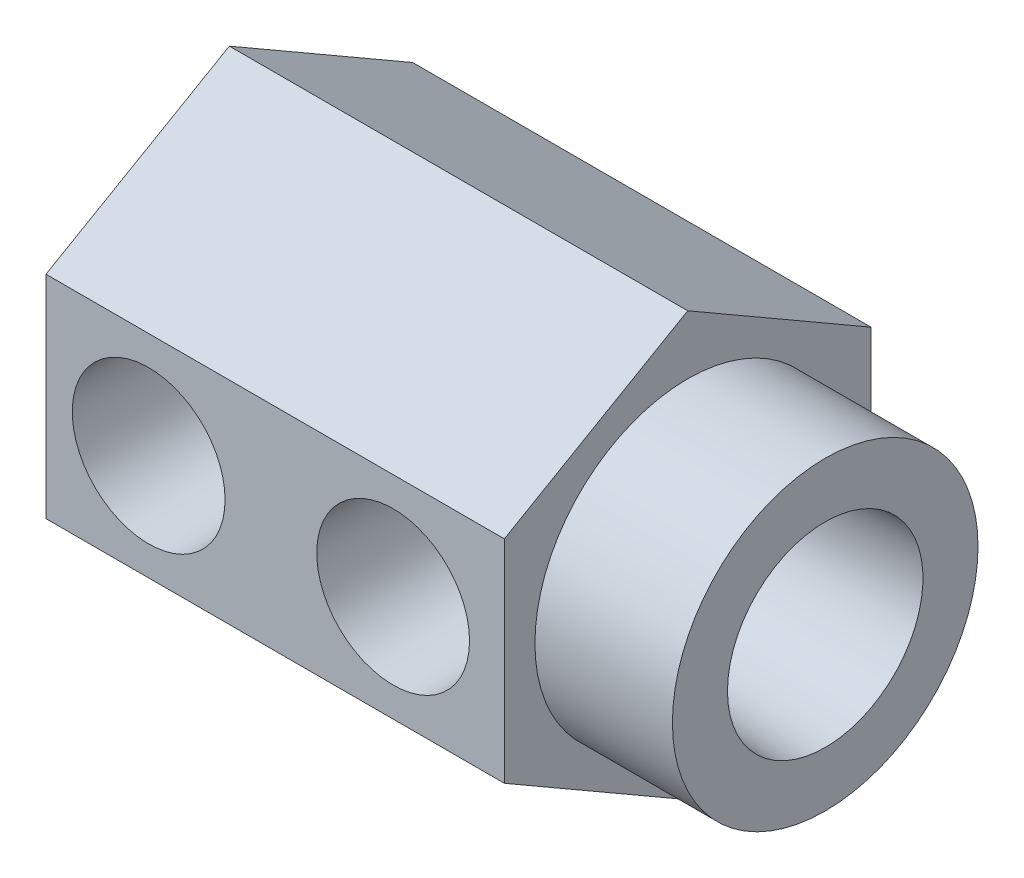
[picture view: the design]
ISO-10303-21;
HEADER;
FILE_DESCRIPTION(('STEP AP214'),'2;1');
FILE_NAME('part.step','',(''),(''),'','','');
FILE_SCHEMA(('AUTOMOTIVE_DESIGN { 1 0 10303 214 1 1 1 1 }'));
ENDSEC;
DATA;
#1=APPLICATION_CONTEXT('core data for automotive mechanical design processes');
#2=APPLICATION_PROTOCOL_DEFINITION('international standard','automotive_design',2000,#1);
#3=PRODUCT_CONTEXT('',#1,'mechanical');
#4=PRODUCT('Part','Part','',(#3));
#5=PRODUCT_RELATED_PRODUCT_CATEGORY('part','',(#4));
#6=PRODUCT_DEFINITION_FORMATION('','',#4);
#7=PRODUCT_DEFINITION_CONTEXT('part definition',#1,'design');
#8=PRODUCT_DEFINITION('design','',#6,#7);
#9=PRODUCT_DEFINITION_SHAPE('','',#8);
#10=(LENGTH_UNIT() NAMED_UNIT(*) SI_UNIT(.MILLI.,.METRE.));
#11=(NAMED_UNIT(*) PLANE_ANGLE_UNIT() SI_UNIT($,.RADIAN.));
#12=(NAMED_UNIT(*) SI_UNIT($,.STERADIAN.) SOLID_ANGLE_UNIT());
#13=UNCERTAINTY_MEASURE_WITH_UNIT(LENGTH_MEASURE(1.E-05),#10,'distance_accuracy_value','');
#14=(GEOMETRIC_REPRESENTATION_CONTEXT(3) GLOBAL_UNCERTAINTY_ASSIGNED_CONTEXT((#13)) GLOBAL_UNIT_ASSIGNED_CONTEXT((#10,
#11,#12)) REPRESENTATION_CONTEXT('',''));
#15=CARTESIAN_POINT('',(0.,0.,0.));
#16=DIRECTION('',(0.,0.,1.));
#17=DIRECTION('',(1.,0.,0.));
#18=AXIS2_PLACEMENT_3D('',#15,#16,#17);
#19=CARTESIAN_POINT('',(30.95625,0.,0.));
#20=DIRECTION('',(1.,0.,0.));
#21=DIRECTION('',(0.,0.,-1.));
#22=AXIS2_PLACEMENT_3D('',#19,#20,#21);
#23=PLANE('',#22);
#24=CARTESIAN_POINT('',(30.95625,0.,0.));
#25=DIRECTION('',(1.,0.,0.));
#26=DIRECTION('',(0.,0.,-1.));
#27=AXIS2_PLACEMENT_3D('',#24,#25,#26);
#28=CIRCLE('',#27,7.9375);
#29=CARTESIAN_POINT('',(30.95625,0.,-7.9375));
#30=VERTEX_POINT('',#29);
#31=EDGE_CURVE('E138',#30,#30,#28,.T.);
#32=ORIENTED_EDGE('',*,*,#31,.T.);
#33=EDGE_LOOP('',(#32));
#34=FACE_BOUND('',#33,.T.);
#35=CARTESIAN_POINT('',(30.95625,0.,0.));
#36=DIRECTION('',(-1.,0.,0.));
#37=DIRECTION('',(0.,0.,1.));
#38=AXIS2_PLACEMENT_3D('',#35,#36,#37);
#39=CIRCLE('',#38,5.07746);
#40=CARTESIAN_POINT('',(30.95625,0.,5.07746));
#41=VERTEX_POINT('',#40);
#42=EDGE_CURVE('E364',#41,#41,#39,.T.);
#43=ORIENTED_EDGE('',*,*,#42,.T.);
#44=EDGE_LOOP('',(#43));
#45=FACE_BOUND('',#44,.T.);
#46=ADVANCED_FACE('F34',(#34,#45),#23,.T.);
#47=CARTESIAN_POINT('',(23.8125,-5.4992613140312,-9.525));
#48=DIRECTION('',(1.,0.,0.));
#49=DIRECTION('',(0.,0.,-1.));
#50=AXIS2_PLACEMENT_3D('',#47,#48,#49);
#51=PLANE('',#50);
#52=DIRECTION('',(0.,0.5,-0.866025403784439));
#53=VECTOR('',#52,1.);
#54=CARTESIAN_POINT('',(23.8125,-10.9985226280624,0.));
#55=LINE('',#54,#53);
#56=CARTESIAN_POINT('',(23.8125,-10.9985226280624,0.));
#57=VERTEX_POINT('',#56);
#58=CARTESIAN_POINT('',(23.8125,-5.49926131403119,-9.525));
#59=VERTEX_POINT('',#58);
#60=EDGE_CURVE('E146',#57,#59,#55,.T.);
#61=ORIENTED_EDGE('',*,*,#60,.T.);
#62=DIRECTION('',(0.,1.,0.));
#63=VECTOR('',#62,1.);
#64=CARTESIAN_POINT('',(23.8125,-5.49926131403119,-9.525));
#65=LINE('',#64,#63);
#66=CARTESIAN_POINT('',(23.8125,5.49926131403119,-9.525));
#67=VERTEX_POINT('',#66);
#68=EDGE_CURVE('E96',#59,#67,#65,.T.);
#69=ORIENTED_EDGE('',*,*,#68,.T.);
#70=DIRECTION('',(0.,0.5,0.866025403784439));
#71=VECTOR('',#70,1.);
#72=CARTESIAN_POINT('',(23.8125,5.49926131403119,-9.525));
#73=LINE('',#72,#71);
#74=CARTESIAN_POINT('',(23.8125,10.9985226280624,0.));
#75=VERTEX_POINT('',#74);
#76=EDGE_CURVE('E113',#67,#75,#73,.T.);
#77=ORIENTED_EDGE('',*,*,#76,.T.);
#78=DIRECTION('',(0.,-0.5,0.866025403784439));
#79=VECTOR('',#78,1.);
#80=CARTESIAN_POINT('',(23.8125,10.9985226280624,0.));
#81=LINE('',#80,#79);
#82=CARTESIAN_POINT('',(23.8125,5.49926131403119,9.52500000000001));
#83=VERTEX_POINT('',#82);
#84=EDGE_CURVE('E105',#75,#83,#81,.T.);
#85=ORIENTED_EDGE('',*,*,#84,.T.);
#86=DIRECTION('',(0.,-1.,0.));
#87=VECTOR('',#86,1.);
#88=CARTESIAN_POINT('',(23.8125,5.49926131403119,9.52500000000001));
#89=LINE('',#88,#87);
#90=CARTESIAN_POINT('',(23.8125,-5.49926131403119,9.52500000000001));
#91=VERTEX_POINT('',#90);
#92=EDGE_CURVE('E110',#83,#91,#89,.T.);
#93=ORIENTED_EDGE('',*,*,#92,.T.);
#94=DIRECTION('',(0.,-0.5,-0.866025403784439));
#95=VECTOR('',#94,1.);
#96=CARTESIAN_POINT('',(23.8125,-5.49926131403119,9.52500000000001));
#97=LINE('',#96,#95);
#98=EDGE_CURVE('E60',#91,#57,#97,.T.);
#99=ORIENTED_EDGE('',*,*,#98,.T.);
#100=EDGE_LOOP('',(#61,#69,#77,#85,#93,#99));
#101=FACE_BOUND('',#100,.T.);
#102=CARTESIAN_POINT('',(23.8125,0.,0.));
#103=DIRECTION('',(1.,0.,0.));
#104=DIRECTION('',(0.,0.,-1.));
#105=AXIS2_PLACEMENT_3D('',#102,#103,#104);
#106=CIRCLE('',#105,7.9375);
#107=CARTESIAN_POINT('',(23.8125,0.,-7.9375));
#108=VERTEX_POINT('',#107);
#109=EDGE_CURVE('E361',#108,#108,#106,.T.);
#110=ORIENTED_EDGE('',*,*,#109,.F.);
#111=EDGE_LOOP('',(#110));
#112=FACE_BOUND('',#111,.T.);
#113=ADVANCED_FACE('F107',(#101,#112),#51,.T.);
#114=CARTESIAN_POINT('',(23.8125,-10.9985226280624,0.));
#115=DIRECTION('',(0.,0.866025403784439,0.5));
#116=DIRECTION('',(0.,-0.5,0.866025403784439));
#117=AXIS2_PLACEMENT_3D('',#114,#115,#116);
#118=PLANE('',#117);
#119=DIRECTION('',(0.,0.5,-0.866025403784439));
#120=VECTOR('',#119,1.);
#121=CARTESIAN_POINT('',(0.,-10.9985226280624,0.));
#122=LINE('',#121,#120);
#123=CARTESIAN_POINT('',(0.,-10.9985226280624,0.));
#124=VERTEX_POINT('',#123);
#125=CARTESIAN_POINT('',(0.,-5.49926131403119,-9.525));
#126=VERTEX_POINT('',#125);
#127=EDGE_CURVE('E134',#124,#126,#122,.T.);
#128=ORIENTED_EDGE('',*,*,#127,.T.);
#129=DIRECTION('',(-1.,0.,0.));
#130=VECTOR('',#129,1.);
#131=CARTESIAN_POINT('',(23.8125,-5.49926131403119,-9.525));
#132=LINE('',#131,#130);
#133=EDGE_CURVE('E153',#59,#126,#132,.T.);
#134=ORIENTED_EDGE('',*,*,#133,.F.);
#135=ORIENTED_EDGE('',*,*,#60,.F.);
#136=DIRECTION('',(-1.,0.,0.));
#137=VECTOR('',#136,1.);
#138=CARTESIAN_POINT('',(23.8125,-10.9985226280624,0.));
#139=LINE('',#138,#137);
#140=EDGE_CURVE('E130',#57,#124,#139,.T.);
#141=ORIENTED_EDGE('',*,*,#140,.T.);
#142=EDGE_LOOP('',(#128,#134,#135,#141));
#143=FACE_BOUND('',#142,.T.);
#144=ADVANCED_FACE('F36',(#143),#118,.F.);
#145=CARTESIAN_POINT('',(23.8125,-5.49926131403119,-9.525));
#146=DIRECTION('',(0.,0.,1.));
#147=DIRECTION('',(1.,0.,0.));
#148=AXIS2_PLACEMENT_3D('',#145,#146,#147);
#149=PLANE('',#148);
#150=CARTESIAN_POINT('',(5.334,0.,-9.525));
#151=DIRECTION('',(0.,0.,-1.));
#152=DIRECTION('',(-1.,0.,0.));
#153=AXIS2_PLACEMENT_3D('',#150,#151,#152);
#154=CIRCLE('',#153,3.96875);
#155=CARTESIAN_POINT('',(1.36525,0.,-9.525));
#156=VERTEX_POINT('',#155);
#157=EDGE_CURVE('E204',#156,#156,#154,.T.);
#158=ORIENTED_EDGE('',*,*,#157,.F.);
#159=EDGE_LOOP('',(#158));
#160=FACE_BOUND('',#159,.T.);
#161=DIRECTION('',(0.,1.,0.));
#162=VECTOR('',#161,1.);
#163=CARTESIAN_POINT('',(0.,-5.49926131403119,-9.525));
#164=LINE('',#163,#162);
#165=CARTESIAN_POINT('',(0.,5.49926131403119,-9.525));
#166=VERTEX_POINT('',#165);
#167=EDGE_CURVE('E137',#126,#166,#164,.T.);
#168=ORIENTED_EDGE('',*,*,#167,.T.);
#169=DIRECTION('',(-1.,0.,0.));
#170=VECTOR('',#169,1.);
#171=CARTESIAN_POINT('',(23.8125,5.49926131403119,-9.525));
#172=LINE('',#171,#170);
#173=EDGE_CURVE('E150',#67,#166,#172,.T.);
#174=ORIENTED_EDGE('',*,*,#173,.F.);
#175=ORIENTED_EDGE('',*,*,#68,.F.);
#176=ORIENTED_EDGE('',*,*,#133,.T.);
#177=EDGE_LOOP('',(#168,#174,#175,#176));
#178=FACE_BOUND('',#177,.T.);
#179=ADVANCED_FACE('F344',(#160,#178),#149,.F.);
#180=CARTESIAN_POINT('',(23.8125,5.49926131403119,-9.525));
#181=DIRECTION('',(0.,-0.866025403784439,0.5));
#182=DIRECTION('',(0.,-0.5,-0.866025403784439));
#183=AXIS2_PLACEMENT_3D('',#180,#181,#182);
#184=PLANE('',#183);
#185=DIRECTION('',(0.,0.5,0.866025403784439));
#186=VECTOR('',#185,1.);
#187=CARTESIAN_POINT('',(0.,5.49926131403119,-9.525));
#188=LINE('',#187,#186);
#189=CARTESIAN_POINT('',(0.,10.9985226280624,0.));
#190=VERTEX_POINT('',#189);
#191=EDGE_CURVE('E140',#166,#190,#188,.T.);
#192=ORIENTED_EDGE('',*,*,#191,.T.);
#193=DIRECTION('',(-1.,0.,0.));
#194=VECTOR('',#193,1.);
#195=CARTESIAN_POINT('',(23.8125,10.9985226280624,0.));
#196=LINE('',#195,#194);
#197=EDGE_CURVE('E125',#75,#190,#196,.T.);
#198=ORIENTED_EDGE('',*,*,#197,.F.);
#199=ORIENTED_EDGE('',*,*,#76,.F.);
#200=ORIENTED_EDGE('',*,*,#173,.T.);
#201=EDGE_LOOP('',(#192,#198,#199,#200));
#202=FACE_BOUND('',#201,.T.);
#203=ADVANCED_FACE('F342',(#202),#184,.F.);
#204=CARTESIAN_POINT('',(23.8125,10.9985226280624,0.));
#205=DIRECTION('',(0.,-0.866025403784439,-0.5));
#206=DIRECTION('',(0.,0.5,-0.866025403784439));
#207=AXIS2_PLACEMENT_3D('',#204,#205,#206);
#208=PLANE('',#207);
#209=DIRECTION('',(0.,-0.5,0.866025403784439));
#210=VECTOR('',#209,1.);
#211=CARTESIAN_POINT('',(0.,10.9985226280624,0.));
#212=LINE('',#211,#210);
#213=CARTESIAN_POINT('',(0.,5.49926131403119,9.52500000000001));
#214=VERTEX_POINT('',#213);
#215=EDGE_CURVE('E122',#190,#214,#212,.T.);
#216=ORIENTED_EDGE('',*,*,#215,.T.);
#217=DIRECTION('',(-1.,0.,0.));
#218=VECTOR('',#217,1.);
#219=CARTESIAN_POINT('',(23.8125,5.49926131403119,9.52500000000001));
#220=LINE('',#219,#218);
#221=EDGE_CURVE('E119',#83,#214,#220,.T.);
#222=ORIENTED_EDGE('',*,*,#221,.F.);
#223=ORIENTED_EDGE('',*,*,#84,.F.);
#224=ORIENTED_EDGE('',*,*,#197,.T.);
#225=EDGE_LOOP('',(#216,#222,#223,#224));
#226=FACE_BOUND('',#225,.T.);
#227=ADVANCED_FACE('F120',(#226),#208,.F.);
#228=CARTESIAN_POINT('',(23.8125,5.49926131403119,9.52500000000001));
#229=DIRECTION('',(0.,0.,-1.));
#230=DIRECTION('',(-1.,0.,0.));
#231=AXIS2_PLACEMENT_3D('',#228,#229,#230);
#232=PLANE('',#231);
#233=CARTESIAN_POINT('',(5.334,0.,9.52500000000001));
#234=DIRECTION('',(0.,0.,1.));
#235=DIRECTION('',(1.,0.,0.));
#236=AXIS2_PLACEMENT_3D('',#233,#234,#235);
#237=CIRCLE('',#236,3.96875);
#238=CARTESIAN_POINT('',(9.30275,0.,9.52500000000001));
#239=VERTEX_POINT('',#238);
#240=EDGE_CURVE('E278',#239,#239,#237,.T.);
#241=ORIENTED_EDGE('',*,*,#240,.F.);
#242=EDGE_LOOP('',(#241));
#243=FACE_BOUND('',#242,.T.);
#244=CARTESIAN_POINT('',(18.034,0.,9.52500000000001));
#245=DIRECTION('',(0.,0.,1.));
#246=DIRECTION('',(1.,0.,0.));
#247=AXIS2_PLACEMENT_3D('',#244,#245,#246);
#248=CIRCLE('',#247,3.96875);
#249=CARTESIAN_POINT('',(22.00275,0.,9.52500000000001));
#250=VERTEX_POINT('',#249);
#251=EDGE_CURVE('E265',#250,#250,#248,.T.);
#252=ORIENTED_EDGE('',*,*,#251,.F.);
#253=EDGE_LOOP('',(#252));
#254=FACE_BOUND('',#253,.T.);
#255=DIRECTION('',(0.,-1.,0.));
#256=VECTOR('',#255,1.);
#257=CARTESIAN_POINT('',(0.,5.49926131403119,9.52500000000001));
#258=LINE('',#257,#256);
#259=CARTESIAN_POINT('',(0.,-5.49926131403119,9.52500000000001));
#260=VERTEX_POINT('',#259);
#261=EDGE_CURVE('E143',#214,#260,#258,.T.);
#262=ORIENTED_EDGE('',*,*,#261,.T.);
#263=DIRECTION('',(-1.,0.,0.));
#264=VECTOR('',#263,1.);
#265=CARTESIAN_POINT('',(23.8125,-5.49926131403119,9.52500000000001));
#266=LINE('',#265,#264);
#267=EDGE_CURVE('E126',#91,#260,#266,.T.);
#268=ORIENTED_EDGE('',*,*,#267,.F.);
#269=ORIENTED_EDGE('',*,*,#92,.F.);
#270=ORIENTED_EDGE('',*,*,#221,.T.);
#271=EDGE_LOOP('',(#262,#268,#269,#270));
#272=FACE_BOUND('',#271,.T.);
#273=ADVANCED_FACE('F128',(#243,#254,#272),#232,.F.);
#274=CARTESIAN_POINT('',(23.8125,-5.49926131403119,9.52500000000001));
#275=DIRECTION('',(0.,0.866025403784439,-0.5));
#276=DIRECTION('',(0.,0.5,0.866025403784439));
#277=AXIS2_PLACEMENT_3D('',#274,#275,#276);
#278=PLANE('',#277);
#279=DIRECTION('',(0.,-0.5,-0.866025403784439));
#280=VECTOR('',#279,1.);
#281=CARTESIAN_POINT('',(0.,-5.49926131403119,9.52500000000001));
#282=LINE('',#281,#280);
#283=EDGE_CURVE('E87',#260,#124,#282,.T.);
#284=ORIENTED_EDGE('',*,*,#283,.T.);
#285=ORIENTED_EDGE('',*,*,#140,.F.);
#286=ORIENTED_EDGE('',*,*,#98,.F.);
#287=ORIENTED_EDGE('',*,*,#267,.T.);
#288=EDGE_LOOP('',(#284,#285,#286,#287));
#289=FACE_BOUND('',#288,.T.);
#290=ADVANCED_FACE('F333',(#289),#278,.F.);
#291=CARTESIAN_POINT('',(0.,-5.4992613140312,-9.525));
#292=DIRECTION('',(1.,0.,0.));
#293=DIRECTION('',(0.,0.,-1.));
#294=AXIS2_PLACEMENT_3D('',#291,#292,#293);
#295=PLANE('',#294);
#296=ORIENTED_EDGE('',*,*,#127,.F.);
#297=ORIENTED_EDGE('',*,*,#283,.F.);
#298=ORIENTED_EDGE('',*,*,#261,.F.);
#299=ORIENTED_EDGE('',*,*,#215,.F.);
#300=ORIENTED_EDGE('',*,*,#191,.F.);
#301=ORIENTED_EDGE('',*,*,#167,.F.);
#302=EDGE_LOOP('',(#296,#297,#298,#299,#300,#301));
#303=FACE_BOUND('',#302,.T.);
#304=ADVANCED_FACE('F328',(#303),#295,.F.);
#305=CARTESIAN_POINT('',(30.95625,0.,0.));
#306=DIRECTION('',(-1.,0.,0.));
#307=DIRECTION('',(0.,0.,1.));
#308=AXIS2_PLACEMENT_3D('',#305,#306,#307);
#309=CYLINDRICAL_SURFACE('',#308,7.9375);
#310=ORIENTED_EDGE('',*,*,#31,.F.);
#311=EDGE_LOOP('',(#310));
#312=FACE_BOUND('',#311,.T.);
#313=ORIENTED_EDGE('',*,*,#109,.T.);
#314=EDGE_LOOP('',(#313));
#315=FACE_BOUND('',#314,.T.);
#316=ADVANCED_FACE('F326',(#312,#315),#309,.T.);
#317=CARTESIAN_POINT('',(30.95625,0.,0.));
#318=DIRECTION('',(1.,0.,0.));
#319=DIRECTION('',(0.,0.,-1.));
#320=AXIS2_PLACEMENT_3D('',#317,#318,#319);
#321=CONICAL_SURFACE('',#320,5.07746,0.0523598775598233);
#322=CARTESIAN_POINT('',(23.97125,0.,0.));
#323=DIRECTION('',(-1.,0.,0.));
#324=DIRECTION('',(0.,0.,1.));
#325=AXIS2_PLACEMENT_3D('',#322,#323,#324);
#326=CIRCLE('',#325,4.711391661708);
#327=CARTESIAN_POINT('',(23.97125,0.,4.711391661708));
#328=VERTEX_POINT('',#327);
#329=EDGE_CURVE('E368',#328,#328,#326,.T.);
#330=ORIENTED_EDGE('',*,*,#329,.T.);
#331=EDGE_LOOP('',(#330));
#332=FACE_BOUND('',#331,.T.);
#333=ORIENTED_EDGE('',*,*,#42,.F.);
#334=EDGE_LOOP('',(#333));
#335=FACE_BOUND('',#334,.T.);
#336=ADVANCED_FACE('F325',(#332,#335),#321,.F.);
#337=CARTESIAN_POINT('',(23.97125,0.,-3.41629999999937));
#338=DIRECTION('',(1.,0.,0.));
#339=DIRECTION('',(0.,0.,-1.));
#340=AXIS2_PLACEMENT_3D('',#337,#338,#339);
#341=PLANE('',#340);
#342=CARTESIAN_POINT('',(23.97125,0.,0.));
#343=DIRECTION('',(-1.,0.,0.));
#344=DIRECTION('',(0.,0.,1.));
#345=AXIS2_PLACEMENT_3D('',#342,#343,#344);
#346=CIRCLE('',#345,3.41629999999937);
#347=CARTESIAN_POINT('',(23.97125,0.,3.41629999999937));
#348=VERTEX_POINT('',#347);
#349=EDGE_CURVE('E371',#348,#348,#346,.T.);
#350=ORIENTED_EDGE('',*,*,#349,.T.);
#351=EDGE_LOOP('',(#350));
#352=FACE_BOUND('',#351,.T.);
#353=ORIENTED_EDGE('',*,*,#329,.F.);
#354=EDGE_LOOP('',(#353));
#355=FACE_BOUND('',#354,.T.);
#356=ADVANCED_FACE('F397',(#352,#355),#341,.T.);
#357=CARTESIAN_POINT('',(-5.61637673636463,0.,0.));
#358=DIRECTION('',(-1.,0.,0.));
#359=DIRECTION('',(0.,0.,1.));
#360=AXIS2_PLACEMENT_3D('',#357,#358,#359);
#361=CYLINDRICAL_SURFACE('',#360,3.41629999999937);
#362=CARTESIAN_POINT('',(21.1074,0.,-3.41629999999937));
#363=CARTESIAN_POINT('',(21.1073906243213,0.142457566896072,-3.41629074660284));
#364=CARTESIAN_POINT('',(21.0974162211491,0.284993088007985,-3.40730981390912));
#365=CARTESIAN_POINT('',(21.0582943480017,0.56526004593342,-3.37218076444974));
#366=CARTESIAN_POINT('',(21.0291272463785,0.702986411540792,-3.34601506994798));
#367=CARTESIAN_POINT('',(20.9539481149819,0.968849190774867,-3.27889164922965));
#368=CARTESIAN_POINT('',(20.9080443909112,1.09704102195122,-3.23802905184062));
#369=CARTESIAN_POINT('',(20.8019209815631,1.34250340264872,-3.14421552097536));
#370=CARTESIAN_POINT('',(20.7416960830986,1.45976995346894,-3.09126018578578));
#371=CARTESIAN_POINT('',(20.5830972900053,1.72643638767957,-2.95315649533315));
#372=CARTESIAN_POINT('',(20.4790627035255,1.87015856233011,-2.86356607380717));
#373=CARTESIAN_POINT('',(20.2527087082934,2.13388777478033,-2.67286201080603));
#374=CARTESIAN_POINT('',(20.1303443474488,2.25383477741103,-2.57172018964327));
#375=CARTESIAN_POINT('',(19.9338160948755,2.41742888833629,-2.41516689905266));
#376=CARTESIAN_POINT('',(19.865262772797,2.46975022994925,-2.36151942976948));
#377=CARTESIAN_POINT('',(19.7241991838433,2.56835019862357,-2.25388595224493));
#378=CARTESIAN_POINT('',(19.6516899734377,2.61463042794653,-2.19990003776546));
#379=CARTESIAN_POINT('',(19.5027314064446,2.70111536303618,-2.09279951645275));
#380=CARTESIAN_POINT('',(19.426288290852,2.7413293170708,-2.03968369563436));
#381=CARTESIAN_POINT('',(19.2690478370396,2.81567123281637,-1.93576189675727));
#382=CARTESIAN_POINT('',(19.1882533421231,2.84980310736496,-1.88495444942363));
#383=CARTESIAN_POINT('',(19.0219129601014,2.91164408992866,-1.78793937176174));
#384=CARTESIAN_POINT('',(18.9363825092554,2.93937269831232,-1.74171802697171));
#385=CARTESIAN_POINT('',(18.7596212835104,2.98791621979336,-1.65705658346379));
#386=CARTESIAN_POINT('',(18.6683962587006,3.0087379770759,-1.61860879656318));
#387=CARTESIAN_POINT('',(18.4959301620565,3.03952516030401,-1.55990772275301));
#388=CARTESIAN_POINT('',(18.4156107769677,3.05073125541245,-1.53767680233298));
#389=CARTESIAN_POINT('',(18.2520056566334,3.06675275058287,-1.50548144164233));
#390=CARTESIAN_POINT('',(18.1687284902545,3.0715852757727,-1.4954841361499));
#391=CARTESIAN_POINT('',(18.0010923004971,3.07437135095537,-1.48975286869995));
#392=CARTESIAN_POINT('',(17.9167298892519,3.07228853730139,-1.49409430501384));
#393=CARTESIAN_POINT('',(17.7501821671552,3.06141172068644,-1.51624518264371));
#394=CARTESIAN_POINT('',(17.6680020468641,3.05260298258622,-1.53408419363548));
#395=CARTESIAN_POINT('',(17.4729486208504,3.02398919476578,-1.58994377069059));
#396=CARTESIAN_POINT('',(17.3621398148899,3.00107873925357,-1.63335206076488));
#397=CARTESIAN_POINT('',(17.1485749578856,2.94518173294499,-1.73212104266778));
#398=CARTESIAN_POINT('',(17.0458550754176,2.91215283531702,-1.78753167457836));
#399=CARTESIAN_POINT('',(16.8549976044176,2.83995043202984,-1.89998166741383));
#400=CARTESIAN_POINT('',(16.7663447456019,2.80143104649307,-1.95658047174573));
#401=CARTESIAN_POINT('',(16.5942445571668,2.71699966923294,-2.07223389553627));
#402=CARTESIAN_POINT('',(16.5108012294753,2.67108208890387,-2.13129034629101));
#403=CARTESIAN_POINT('',(16.3488100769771,2.57195064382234,-2.24992301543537));
#404=CARTESIAN_POINT('',(16.2702606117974,2.51873924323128,-2.30949905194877));
#405=CARTESIAN_POINT('',(16.1179919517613,2.40493916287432,-2.42778009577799));
#406=CARTESIAN_POINT('',(16.0442737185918,2.34434902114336,-2.486484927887));
#407=CARTESIAN_POINT('',(15.8513952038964,2.17001201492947,-2.64271694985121));
#408=CARTESIAN_POINT('',(15.7370373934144,2.04901466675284,-2.73828635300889));
#409=CARTESIAN_POINT('',(15.5262353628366,1.78474938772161,-2.91739010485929));
#410=CARTESIAN_POINT('',(15.4297539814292,1.64152882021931,-3.00094933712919));
#411=CARTESIAN_POINT('',(15.2789335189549,1.36887485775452,-3.13284294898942));
#412=CARTESIAN_POINT('',(15.2200027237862,1.2437766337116,-3.18486295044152));
#413=CARTESIAN_POINT('',(15.1184268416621,0.982245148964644,-3.27495514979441));
#414=CARTESIAN_POINT('',(15.0757725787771,0.845818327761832,-3.31303520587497));
#415=CARTESIAN_POINT('',(15.0259678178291,0.634703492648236,-3.35760685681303));
#416=CARTESIAN_POINT('',(15.0116986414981,0.562929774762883,-3.37040024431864));
#417=CARTESIAN_POINT('',(14.9882617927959,0.417909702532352,-3.39143210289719));
#418=CARTESIAN_POINT('',(14.9790916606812,0.344664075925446,-3.39967277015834));
#419=CARTESIAN_POINT('',(14.9660509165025,0.197338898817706,-3.41139583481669));
#420=CARTESIAN_POINT('',(14.9621790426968,0.123259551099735,-3.41487936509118));
#421=CARTESIAN_POINT('',(14.9598058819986,-0.0250305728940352,-3.41701450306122));
#422=CARTESIAN_POINT('',(14.961304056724,-0.0992413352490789,-3.41566659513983));
#423=CARTESIAN_POINT('',(14.9728587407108,-0.303677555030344,-3.40527356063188));
#424=CARTESIAN_POINT('',(14.988577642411,-0.433397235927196,-3.39113605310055));
#425=CARTESIAN_POINT('',(15.0356843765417,-0.687487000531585,-3.34889668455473));
#426=CARTESIAN_POINT('',(15.0670744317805,-0.811856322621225,-3.32079284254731));
#427=CARTESIAN_POINT('',(15.1447062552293,-1.055723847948,-3.25161743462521));
#428=CARTESIAN_POINT('',(15.1913035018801,-1.17501935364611,-3.21023592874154));
#429=CARTESIAN_POINT('',(15.2969019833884,-1.4035545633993,-3.1171157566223));
#430=CARTESIAN_POINT('',(15.3559084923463,-1.51278996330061,-3.06537268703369));
#431=CARTESIAN_POINT('',(15.5164413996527,-1.77233980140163,-2.92593514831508));
#432=CARTESIAN_POINT('',(15.6244943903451,-1.91596062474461,-2.83318323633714));
#433=CARTESIAN_POINT('',(15.8002449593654,-2.11279907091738,-2.68588349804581));
#434=CARTESIAN_POINT('',(15.8612383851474,-2.17541615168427,-2.63531576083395));
#435=CARTESIAN_POINT('',(15.9874380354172,-2.29453449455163,-2.53227207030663));
#436=CARTESIAN_POINT('',(16.0526427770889,-2.35103789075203,-2.47979679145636));
#437=CARTESIAN_POINT('',(16.1885856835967,-2.45926087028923,-2.37256880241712));
#438=CARTESIAN_POINT('',(16.2594176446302,-2.51083752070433,-2.31779153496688));
#439=CARTESIAN_POINT('',(16.4051624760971,-2.60774464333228,-2.20819337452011));
#440=CARTESIAN_POINT('',(16.480074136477,-2.653076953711,-2.1533724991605));
#441=CARTESIAN_POINT('',(16.6340283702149,-2.73743692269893,-2.04505374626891));
#442=CARTESIAN_POINT('',(16.7130627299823,-2.77647652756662,-1.99155352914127));
#443=CARTESIAN_POINT('',(16.8757896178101,-2.84819921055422,-1.88755018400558));
#444=CARTESIAN_POINT('',(16.9594781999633,-2.88088757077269,-1.83704458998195));
#445=CARTESIAN_POINT('',(17.127249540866,-2.93785270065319,-1.74439302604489));
#446=CARTESIAN_POINT('',(17.2110250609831,-2.96250867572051,-1.70193139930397));
#447=CARTESIAN_POINT('',(17.3839551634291,-3.00518460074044,-1.62538880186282));
#448=CARTESIAN_POINT('',(17.4731014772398,-3.02321446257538,-1.59129533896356));
#449=CARTESIAN_POINT('',(17.6419171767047,-3.04928140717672,-1.54067461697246));
#450=CARTESIAN_POINT('',(17.720803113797,-3.058459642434,-1.52220345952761));
#451=CARTESIAN_POINT('',(17.8808819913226,-3.07062681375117,-1.49751869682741));
#452=CARTESIAN_POINT('',(17.9620695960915,-3.07362903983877,-1.4912787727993));
#453=CARTESIAN_POINT('',(18.1245222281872,-3.07314284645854,-1.49227919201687));
#454=CARTESIAN_POINT('',(18.2057870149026,-3.06963972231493,-1.49955007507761));
#455=CARTESIAN_POINT('',(18.3658523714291,-3.05649264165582,-1.52616057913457));
#456=CARTESIAN_POINT('',(18.4446471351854,-3.0468352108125,-1.54552667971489));
#457=CARTESIAN_POINT('',(18.6411074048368,-3.01527767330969,-1.60652028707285));
#458=CARTESIAN_POINT('',(18.7561047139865,-2.98955853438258,-1.65453716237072));
#459=CARTESIAN_POINT('',(18.9774267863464,-2.92729500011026,-1.76237184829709));
#460=CARTESIAN_POINT('',(19.0837112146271,-2.8907035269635,-1.82224059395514));
#461=CARTESIAN_POINT('',(19.278873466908,-2.81176552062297,-1.94157617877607));
#462=CARTESIAN_POINT('',(19.3684410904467,-2.77031588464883,-2.00052360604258));
#463=CARTESIAN_POINT('',(19.5422377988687,-2.67966824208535,-2.12041024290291));
#464=CARTESIAN_POINT('',(19.6264630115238,-2.63046470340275,-2.18135084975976));
#465=CARTESIAN_POINT('',(19.7897700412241,-2.52438599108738,-2.30328258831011));
#466=CARTESIAN_POINT('',(19.8688559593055,-2.46751704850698,-2.36427363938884));
#467=CARTESIAN_POINT('',(20.0218913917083,-2.34597990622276,-2.48491905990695));
#468=CARTESIAN_POINT('',(20.0958401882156,-2.28131062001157,-2.54457324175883));
#469=CARTESIAN_POINT('',(20.2819798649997,-2.1018729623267,-2.69710341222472));
#470=CARTESIAN_POINT('',(20.3898225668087,-1.98069618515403,-2.7879259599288));
#471=CARTESIAN_POINT('',(20.5880588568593,-1.71744050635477,-2.95735105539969));
#472=CARTESIAN_POINT('',(20.6784836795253,-1.57539984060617,-3.03597542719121));
#473=CARTESIAN_POINT('',(20.8203169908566,-1.3039919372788,-3.16037812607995));
#474=CARTESIAN_POINT('',(20.8759338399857,-1.17841159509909,-3.20958492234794));
#475=CARTESIAN_POINT('',(20.9707669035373,-0.916765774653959,-3.29384915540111));
#476=CARTESIAN_POINT('',(21.0100080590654,-0.780716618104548,-3.32892810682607));
#477=CARTESIAN_POINT('',(21.0620001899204,-0.536986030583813,-3.37550132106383));
#478=CARTESIAN_POINT('',(21.0789513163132,-0.430897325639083,-3.39072586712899));
#479=CARTESIAN_POINT('',(21.1016550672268,-0.216554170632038,-3.41112897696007));
#480=CARTESIAN_POINT('',(21.1074071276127,-0.108299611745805,-3.41630703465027));
#481=CARTESIAN_POINT('',(21.1074,0.,-3.41629999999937));
#482=B_SPLINE_CURVE_WITH_KNOTS('',3,(#362,#363,#364,#365,#366,#367,#368,#369,#370,#371,#372,
#373,#374,#375,#376,#377,#378,#379,#380,#381,#382,#383,#384,#385,#386,#387,#388,#389,#390,#391,
#392,#393,#394,#395,#396,#397,#398,#399,#400,#401,#402,#403,#404,#405,#406,#407,#408,#409,#410,
#411,#412,#413,#414,#415,#416,#417,#418,#419,#420,#421,#422,#423,#424,#425,#426,#427,#428,#429,
#430,#431,#432,#433,#434,#435,#436,#437,#438,#439,#440,#441,#442,#443,#444,#445,#446,#447,#448,
#449,#450,#451,#452,#453,#454,#455,#456,#457,#458,#459,#460,#461,#462,#463,#464,#465,#466,#467,
#468,#469,#470,#471,#472,#473,#474,#475,#476,#477,#478,#479,#480,#481),.UNSPECIFIED.,.T.,.F.,(4,
2,2,2,2,2,2,2,2,2,2,2,2,2,2,2,2,2,2,2,2,2,2,2,2,2,2,2,2,2,2,2,2,2,2,2,2,2,2,2,2,2,2,2,2,2,2,2,2,
2,2,2,2,2,2,2,2,2,2,4),(0.,0.426905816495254,0.854248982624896,1.27887444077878,1.7036547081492,
2.29674049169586,2.89130532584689,3.19578881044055,3.50019137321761,3.80412506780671,
4.10786251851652,4.41066240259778,4.71316133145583,4.96448724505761,5.21513648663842,
5.46710582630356,5.71962876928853,6.08116121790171,6.4442278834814,6.77982012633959,
7.11566707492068,7.45140083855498,7.78720123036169,8.36088009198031,8.93335267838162,
9.37493030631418,9.8162586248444,10.0388467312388,10.2613273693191,10.4837550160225,
10.7061603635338,11.0984232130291,11.4907417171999,11.8929806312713,12.2953908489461,
12.8985583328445,13.201316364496,13.5039683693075,13.8137045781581,14.1233494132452,
14.4323993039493,14.7411910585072,15.0319860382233,15.3223442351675,15.5659778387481,
15.8090866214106,16.0527455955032,16.2969398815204,16.6765146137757,17.0577574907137,
17.4021870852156,17.7468635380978,18.0912614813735,18.4357074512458,18.9913179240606,
19.5459225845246,19.9819097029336,20.4172303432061,20.7417578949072,21.0663017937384),.UNSPECIFIED.);
#483=CARTESIAN_POINT('',(21.1074,0.,-3.41629999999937));
#484=VERTEX_POINT('',#483);
#485=EDGE_CURVE('E200',#484,#484,#482,.T.);
#486=ORIENTED_EDGE('',*,*,#485,.F.);
#487=EDGE_LOOP('',(#486));
#488=FACE_BOUND('',#487,.T.);
#489=CARTESIAN_POINT('',(14.9600111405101,-2.16968283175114,2.63886000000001));
#490=CARTESIAN_POINT('',(14.9150189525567,-2.10853489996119,2.68912119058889));
#491=CARTESIAN_POINT('',(14.8712851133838,-2.04512144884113,2.73770979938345));
#492=CARTESIAN_POINT('',(14.7867636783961,-1.91360919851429,2.83121060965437));
#493=CARTESIAN_POINT('',(14.7459805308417,-1.84550361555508,2.87611727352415));
#494=CARTESIAN_POINT('',(14.6308304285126,-1.63768444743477,3.00247948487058));
#495=CARTESIAN_POINT('',(14.5613875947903,-1.4914374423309,3.07810382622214));
#496=CARTESIAN_POINT('',(14.462957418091,-1.24045751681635,3.18488334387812));
#497=CARTESIAN_POINT('',(14.4285115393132,-1.14040554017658,3.22213569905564));
#498=CARTESIAN_POINT('',(14.3673839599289,-0.933479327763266,3.28811991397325));
#499=CARTESIAN_POINT('',(14.3408265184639,-0.826525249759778,3.31671553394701));
#500=CARTESIAN_POINT('',(14.31905,-0.71730556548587,3.34014646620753));
#501=B_SPLINE_CURVE_WITH_KNOTS('',3,(#489,#490,#491,#492,#493,#494,#495,#496,#497,#498,#499,
#500),.UNSPECIFIED.,.F.,.F.,(4,2,2,2,2,4),(0.,0.273021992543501,0.546447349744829,
1.07976341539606,1.41559322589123,1.75646224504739),.UNSPECIFIED.);
#502=CARTESIAN_POINT('',(14.9598321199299,-2.16943956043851,2.63906000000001));
#503=VERTEX_POINT('',#502);
#504=CARTESIAN_POINT('',(14.31925,-0.718306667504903,3.33993131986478));
#505=VERTEX_POINT('',#504);
#506=EDGE_CURVE('E43',#503,#505,#501,.T.);
#507=ORIENTED_EDGE('',*,*,#506,.F.);
#508=DIRECTION('',(-1.,0.,0.));
#509=VECTOR('',#508,1.);
#510=CARTESIAN_POINT('',(-5.61637673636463,-2.16943956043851,2.63906000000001));
#511=LINE('',#510,#509);
#512=CARTESIAN_POINT('',(15.8570021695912,-2.16943956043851,2.63906000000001));
#513=VERTEX_POINT('',#512);
#514=EDGE_CURVE('E195',#513,#503,#511,.T.);
#515=ORIENTED_EDGE('',*,*,#514,.F.);
#516=CARTESIAN_POINT('',(20.2109978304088,-2.16943956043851,2.63906000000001));
#517=CARTESIAN_POINT('',(20.1714390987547,-2.20913157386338,2.60643078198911));
#518=CARTESIAN_POINT('',(20.1309974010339,-2.24754794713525,2.57334996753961));
#519=CARTESIAN_POINT('',(20.0484095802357,-2.32185933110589,2.50650631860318));
#520=CARTESIAN_POINT('',(20.006263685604,-2.35775467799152,2.47274357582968));
#521=CARTESIAN_POINT('',(19.8771442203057,-2.46188193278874,2.37059140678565));
#522=CARTESIAN_POINT('',(19.7876748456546,-2.52636926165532,2.30149304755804));
#523=CARTESIAN_POINT('',(19.6003931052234,-2.64666702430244,2.16215138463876));
#524=CARTESIAN_POINT('',(19.5024493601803,-2.70227739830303,2.09191292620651));
#525=CARTESIAN_POINT('',(19.2993704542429,-2.80311808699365,1.95469595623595));
#526=CARTESIAN_POINT('',(19.1942473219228,-2.84836523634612,1.88771229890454));
#527=CARTESIAN_POINT('',(19.0022026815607,-2.91823431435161,1.77713104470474));
#528=CARTESIAN_POINT('',(18.9171298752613,-2.94519355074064,1.73182401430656));
#529=CARTESIAN_POINT('',(18.7415661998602,-2.99221635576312,1.6492389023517));
#530=CARTESIAN_POINT('',(18.6510955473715,-3.01230396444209,1.611933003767));
#531=CARTESIAN_POINT('',(18.479793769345,-3.04192325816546,1.55520804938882));
#532=CARTESIAN_POINT('',(18.399836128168,-3.05264996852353,1.53385305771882));
#533=CARTESIAN_POINT('',(18.2371057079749,-3.06776305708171,1.50341003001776));
#534=CARTESIAN_POINT('',(18.1543407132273,-3.07216570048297,1.49429052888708));
#535=CARTESIAN_POINT('',(17.9879763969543,-3.07418502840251,1.49013496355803));
#536=CARTESIAN_POINT('',(17.9043749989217,-3.07177123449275,1.49516215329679));
#537=CARTESIAN_POINT('',(17.7394069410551,-3.06037271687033,1.51834630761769));
#538=CARTESIAN_POINT('',(17.6580460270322,-3.05137248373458,1.53653426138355));
#539=CARTESIAN_POINT('',(17.462793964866,-3.02212841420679,1.59350200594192));
#540=CARTESIAN_POINT('',(17.3510982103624,-2.99862096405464,1.63790025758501));
#541=CARTESIAN_POINT('',(17.1358591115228,-2.94136683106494,1.738631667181));
#542=CARTESIAN_POINT('',(17.0323554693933,-2.90757372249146,1.79501858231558));
#543=CARTESIAN_POINT('',(16.8403729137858,-2.83385543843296,1.90909274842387));
#544=CARTESIAN_POINT('',(16.751352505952,-2.79462108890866,1.96632937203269));
#545=CARTESIAN_POINT('',(16.5785511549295,-2.70864872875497,2.08316986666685));
#546=CARTESIAN_POINT('',(16.4947748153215,-2.66190425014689,2.14277574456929));
#547=CARTESIAN_POINT('',(16.3323908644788,-2.56113540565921,2.26225314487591));
#548=CARTESIAN_POINT('',(16.2537693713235,-2.50713189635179,2.32212344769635));
#549=CARTESIAN_POINT('',(16.101425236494,-2.39166656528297,2.44087942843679));
#550=CARTESIAN_POINT('',(16.0277008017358,-2.3302074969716,2.49976546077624));
#551=CARTESIAN_POINT('',(15.9396834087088,-2.2494778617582,2.57126127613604));
#552=CARTESIAN_POINT('',(15.9229307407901,-2.23376438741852,2.58492578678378));
#553=CARTESIAN_POINT('',(15.8897359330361,-2.20191915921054,2.61210550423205));
#554=CARTESIAN_POINT('',(15.8732935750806,-2.18578771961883,2.62562081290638));
#555=CARTESIAN_POINT('',(15.8570021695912,-2.16943956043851,2.63906000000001));
#556=B_SPLINE_CURVE_WITH_KNOTS('',3,(#516,#517,#518,#519,#520,#521,#522,#523,#524,#525,#526,
#527,#528,#529,#530,#531,#532,#533,#534,#535,#536,#537,#538,#539,#540,#541,#542,#543,#544,#545,
#546,#547,#548,#549,#550,#551,#552,#553,#554,#555),.UNSPECIFIED.,.F.,.F.,(4,2,2,2,2,2,2,2,2,2,2,
2,2,2,2,2,2,2,2,4),(0.,0.194491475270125,0.388956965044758,0.778799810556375,1.17646468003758,
1.57347890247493,1.87324748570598,2.17195635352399,2.42136433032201,2.67012968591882,
2.92000910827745,3.17047883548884,3.53582839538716,3.90285210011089,4.24102539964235,
4.57949152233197,4.9170051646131,5.25439453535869,5.33456943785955,5.41468571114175),.UNSPECIFIED.);
#557=CARTESIAN_POINT('',(20.2109978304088,-2.16943956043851,2.63906000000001));
#558=VERTEX_POINT('',#557);
#559=EDGE_CURVE('E196',#558,#513,#556,.T.);
#560=ORIENTED_EDGE('',*,*,#559,.F.);
#561=CARTESIAN_POINT('',(21.1081678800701,-2.16943956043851,2.63906000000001));
#562=VERTEX_POINT('',#561);
#563=EDGE_CURVE('E418',#562,#558,#511,.T.);
#564=ORIENTED_EDGE('',*,*,#563,.F.);
#565=CARTESIAN_POINT('',(21.1079888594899,2.16968283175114,2.63886000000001));
#566=CARTESIAN_POINT('',(21.1520619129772,2.10978059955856,2.68809472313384));
#567=CARTESIAN_POINT('',(21.1949245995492,2.04771437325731,2.73572086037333));
#568=CARTESIAN_POINT('',(21.277820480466,1.91910612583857,2.82743992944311));
#569=CARTESIAN_POINT('',(21.3178504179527,1.85255911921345,2.87152880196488));
#570=CARTESIAN_POINT('',(21.43365387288,1.64488764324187,2.99864636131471));
#571=CARTESIAN_POINT('',(21.5042906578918,1.49686045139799,3.07558131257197));
#572=CARTESIAN_POINT('',(21.5965672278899,1.26231099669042,3.1756909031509));
#573=CARTESIAN_POINT('',(21.6251366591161,1.18167944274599,3.20660868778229));
#574=CARTESIAN_POINT('',(21.676992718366,1.01679743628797,3.26263564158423));
#575=CARTESIAN_POINT('',(21.7002826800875,0.932549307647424,3.28774847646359));
#576=CARTESIAN_POINT('',(21.7409398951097,0.761401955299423,3.33153788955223));
#577=CARTESIAN_POINT('',(21.7583319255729,0.674515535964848,3.35024139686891));
#578=CARTESIAN_POINT('',(21.7868650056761,0.498555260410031,3.38090469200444));
#579=CARTESIAN_POINT('',(21.7980075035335,0.409481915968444,3.39286604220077));
#580=CARTESIAN_POINT('',(21.8125733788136,0.243238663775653,3.40849786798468));
#581=CARTESIAN_POINT('',(21.8168878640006,0.166234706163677,3.41312559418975));
#582=CARTESIAN_POINT('',(21.8206404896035,0.0119430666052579,3.41715078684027));
#583=CARTESIAN_POINT('',(21.8200770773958,-0.0653446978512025,3.41654658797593));
#584=CARTESIAN_POINT('',(21.8140798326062,-0.219500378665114,3.4101133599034));
#585=CARTESIAN_POINT('',(21.8086468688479,-0.296368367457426,3.40428526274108));
#586=CARTESIAN_POINT('',(21.7930369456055,-0.449069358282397,3.38752932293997));
#587=CARTESIAN_POINT('',(21.7828581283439,-0.524901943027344,3.37659948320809));
#588=CARTESIAN_POINT('',(21.7475961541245,-0.737278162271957,3.33870233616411));
#589=CARTESIAN_POINT('',(21.7171545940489,-0.871970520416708,3.30595350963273));
#590=CARTESIAN_POINT('',(21.6428817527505,-1.13313444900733,3.22581326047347));
#591=CARTESIAN_POINT('',(21.5990255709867,-1.25959019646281,3.17839460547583));
#592=CARTESIAN_POINT('',(21.4895347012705,-1.52855418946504,3.0595117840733));
#593=CARTESIAN_POINT('',(21.4212452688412,-1.66867331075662,2.98507023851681));
#594=CARTESIAN_POINT('',(21.3097598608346,-1.86614519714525,2.86262107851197));
#595=CARTESIAN_POINT('',(21.2711796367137,-1.92973148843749,2.82010703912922));
#596=CARTESIAN_POINT('',(21.1914307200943,-2.05277064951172,2.73183852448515));
#597=CARTESIAN_POINT('',(21.1502650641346,-2.11222820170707,2.68608784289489));
#598=CARTESIAN_POINT('',(21.1079888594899,-2.16968283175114,2.63886000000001));
#599=B_SPLINE_CURVE_WITH_KNOTS('',3,(#565,#566,#567,#568,#569,#570,#571,#572,#573,#574,#575,
#576,#577,#578,#579,#580,#581,#582,#583,#584,#585,#586,#587,#588,#589,#590,#591,#592,#593,#594,
#595,#596,#597,#598),.UNSPECIFIED.,.F.,.F.,(4,2,2,2,2,2,2,2,2,2,2,2,2,2,2,2,4),(0.,
0.267435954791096,0.535174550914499,1.07570322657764,1.34825580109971,1.62063579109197,
1.89185691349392,2.16301515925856,2.39448525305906,2.62602902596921,2.85753149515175,
3.08912466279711,3.51294151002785,3.93754988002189,4.45339356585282,4.71024270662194,
4.96679562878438),.UNSPECIFIED.);
#600=CARTESIAN_POINT('',(21.1081678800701,2.16943956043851,2.63906000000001));
#601=VERTEX_POINT('',#600);
#602=EDGE_CURVE('E183',#601,#562,#599,.T.);
#603=ORIENTED_EDGE('',*,*,#602,.F.);
#604=DIRECTION('',(-1.,0.,0.));
#605=VECTOR('',#604,1.);
#606=CARTESIAN_POINT('',(-5.61637673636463,2.16943956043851,2.63906000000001));
#607=LINE('',#606,#605);
#608=CARTESIAN_POINT('',(20.2109978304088,2.16943956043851,2.63906000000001));
#609=VERTEX_POINT('',#608);
#610=EDGE_CURVE('E222',#609,#601,#607,.F.);
#611=ORIENTED_EDGE('',*,*,#610,.F.);
#612=CARTESIAN_POINT('',(15.8570021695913,2.16943956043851,2.63906000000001));
#613=CARTESIAN_POINT('',(15.8965609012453,2.20913157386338,2.60643078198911));
#614=CARTESIAN_POINT('',(15.9370025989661,2.24754794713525,2.57334996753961));
#615=CARTESIAN_POINT('',(16.0195904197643,2.32185933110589,2.50650631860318));
#616=CARTESIAN_POINT('',(16.061736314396,2.35775467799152,2.47274357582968));
#617=CARTESIAN_POINT('',(16.1908557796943,2.46188193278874,2.37059140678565));
#618=CARTESIAN_POINT('',(16.2803251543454,2.52636926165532,2.30149304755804));
#619=CARTESIAN_POINT('',(16.4676068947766,2.64666702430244,2.16215138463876));
#620=CARTESIAN_POINT('',(16.5655506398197,2.70227739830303,2.09191292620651));
#621=CARTESIAN_POINT('',(16.7686295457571,2.80311808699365,1.95469595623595));
#622=CARTESIAN_POINT('',(16.8737526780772,2.84836523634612,1.88771229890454));
#623=CARTESIAN_POINT('',(17.0657973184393,2.91823431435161,1.77713104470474));
#624=CARTESIAN_POINT('',(17.1508701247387,2.94519355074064,1.73182401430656));
#625=CARTESIAN_POINT('',(17.3264338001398,2.99221635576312,1.6492389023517));
#626=CARTESIAN_POINT('',(17.4169044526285,3.01230396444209,1.611933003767));
#627=CARTESIAN_POINT('',(17.588206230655,3.04192325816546,1.55520804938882));
#628=CARTESIAN_POINT('',(17.668163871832,3.05264996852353,1.53385305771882));
#629=CARTESIAN_POINT('',(17.8308942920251,3.06776305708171,1.50341003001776));
#630=CARTESIAN_POINT('',(17.9136592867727,3.07216570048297,1.49429052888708));
#631=CARTESIAN_POINT('',(18.0800236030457,3.07418502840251,1.49013496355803));
#632=CARTESIAN_POINT('',(18.1636250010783,3.07177123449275,1.49516215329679));
#633=CARTESIAN_POINT('',(18.3285930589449,3.06037271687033,1.51834630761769));
#634=CARTESIAN_POINT('',(18.4099539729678,3.05137248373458,1.53653426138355));
#635=CARTESIAN_POINT('',(18.605206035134,3.02212841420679,1.59350200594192));
#636=CARTESIAN_POINT('',(18.7169017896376,2.99862096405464,1.63790025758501));
#637=CARTESIAN_POINT('',(18.9321408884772,2.94136683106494,1.738631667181));
#638=CARTESIAN_POINT('',(19.0356445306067,2.90757372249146,1.79501858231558));
#639=CARTESIAN_POINT('',(19.2276270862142,2.83385543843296,1.90909274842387));
#640=CARTESIAN_POINT('',(19.316647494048,2.79462108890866,1.9663293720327));
#641=CARTESIAN_POINT('',(19.4894488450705,2.70864872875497,2.08316986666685));
#642=CARTESIAN_POINT('',(19.5732251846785,2.66190425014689,2.14277574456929));
#643=CARTESIAN_POINT('',(19.7356091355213,2.56113540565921,2.26225314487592));
#644=CARTESIAN_POINT('',(19.8142306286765,2.50713189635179,2.32212344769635));
#645=CARTESIAN_POINT('',(19.966574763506,2.39166656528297,2.44087942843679));
#646=CARTESIAN_POINT('',(20.0402991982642,2.3302074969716,2.49976546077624));
#647=CARTESIAN_POINT('',(20.1283165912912,2.2494778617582,2.57126127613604));
#648=CARTESIAN_POINT('',(20.1450692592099,2.23376438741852,2.58492578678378));
#649=CARTESIAN_POINT('',(20.1782640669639,2.20191915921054,2.61210550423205));
#650=CARTESIAN_POINT('',(20.1947064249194,2.18578771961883,2.62562081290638));
#651=CARTESIAN_POINT('',(20.2109978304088,2.16943956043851,2.63906000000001));
#652=B_SPLINE_CURVE_WITH_KNOTS('',3,(#612,#613,#614,#615,#616,#617,#618,#619,#620,#621,#622,
#623,#624,#625,#626,#627,#628,#629,#630,#631,#632,#633,#634,#635,#636,#637,#638,#639,#640,#641,
#642,#643,#644,#645,#646,#647,#648,#649,#650,#651),.UNSPECIFIED.,.F.,.F.,(4,2,2,2,2,2,2,2,2,2,2,
2,2,2,2,2,2,2,2,4),(0.,0.194491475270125,0.388956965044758,0.778799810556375,1.17646468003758,
1.57347890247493,1.87324748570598,2.17195635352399,2.42136433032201,2.67012968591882,
2.92000910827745,3.17047883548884,3.53582839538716,3.90285210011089,4.24102539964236,
4.57949152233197,4.9170051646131,5.25439453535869,5.33456943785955,5.41468571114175),.UNSPECIFIED.);
#653=CARTESIAN_POINT('',(15.8570021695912,2.16943956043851,2.63906000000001));
#654=VERTEX_POINT('',#653);
#655=EDGE_CURVE('E217',#654,#609,#652,.T.);
#656=ORIENTED_EDGE('',*,*,#655,.F.);
#657=CARTESIAN_POINT('',(14.9598321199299,2.16943956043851,2.63906000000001));
#658=VERTEX_POINT('',#657);
#659=EDGE_CURVE('E162',#658,#654,#607,.F.);
#660=ORIENTED_EDGE('',*,*,#659,.F.);
#661=CARTESIAN_POINT('',(14.3190500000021,0.717305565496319,3.34014646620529));
#662=CARTESIAN_POINT('',(14.3364536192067,0.804574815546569,3.3214224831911));
#663=CARTESIAN_POINT('',(14.3569233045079,0.89046276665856,3.29938425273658));
#664=CARTESIAN_POINT('',(14.4033910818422,1.05879777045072,3.24926493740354));
#665=CARTESIAN_POINT('',(14.4293821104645,1.14124905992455,3.22119157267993));
#666=CARTESIAN_POINT('',(14.4857213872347,1.3005196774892,3.16020256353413));
#667=CARTESIAN_POINT('',(14.5159634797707,1.37742215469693,3.12740451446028));
#668=CARTESIAN_POINT('',(14.5806418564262,1.52718172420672,3.05706790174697));
#669=CARTESIAN_POINT('',(14.6150785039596,1.6000384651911,3.01952892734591));
#670=CARTESIAN_POINT('',(14.6972440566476,1.76031582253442,2.92966503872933));
#671=CARTESIAN_POINT('',(14.7460720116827,1.84645493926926,2.87606326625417));
#672=CARTESIAN_POINT('',(14.8492506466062,2.01291647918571,2.7621702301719));
#673=CARTESIAN_POINT('',(14.9036695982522,2.09313954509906,2.70179516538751));
#674=CARTESIAN_POINT('',(14.9600111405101,2.16968283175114,2.63886000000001));
#675=B_SPLINE_CURVE_WITH_KNOTS('',3,(#661,#662,#663,#664,#665,#666,#667,#668,#669,#670,#671,
#672,#673,#674),.UNSPECIFIED.,.F.,.F.,(4,2,2,2,2,2,4),(0.,0.272606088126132,0.544865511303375,
0.811248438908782,1.07765446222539,1.41492932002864,1.75696860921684),.UNSPECIFIED.);
#676=CARTESIAN_POINT('',(14.31925,0.718306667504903,3.33993131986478));
#677=VERTEX_POINT('',#676);
#678=EDGE_CURVE('E155',#677,#658,#675,.T.);
#679=ORIENTED_EDGE('',*,*,#678,.F.);
#680=CARTESIAN_POINT('',(14.31925,0.,0.));
#681=DIRECTION('',(-1.,0.,0.));
#682=DIRECTION('',(0.,0.,1.));
#683=AXIS2_PLACEMENT_3D('',#680,#681,#682);
#684=CIRCLE('',#683,3.41629999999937);
#685=EDGE_CURVE('E374',#677,#505,#684,.T.);
#686=ORIENTED_EDGE('',*,*,#685,.T.);
#687=EDGE_LOOP('',(#507,#515,#560,#564,#603,#611,#656,#660,#679,#686));
#688=FACE_BOUND('',#687,.T.);
#689=ORIENTED_EDGE('',*,*,#349,.F.);
#690=EDGE_LOOP('',(#689));
#691=FACE_BOUND('',#690,.T.);
#692=ADVANCED_FACE('F164',(#488,#688,#691),#361,.F.);
#693=CARTESIAN_POINT('',(14.31925,0.,0.));
#694=DIRECTION('',(1.,0.,0.));
#695=DIRECTION('',(0.,0.,-1.));
#696=AXIS2_PLACEMENT_3D('',#693,#694,#695);
#697=PLANE('',#696);
#698=CARTESIAN_POINT('',(14.31925,0.,0.));
#699=DIRECTION('',(1.,0.,0.));
#700=DIRECTION('',(0.,0.,-1.));
#701=AXIS2_PLACEMENT_3D('',#698,#699,#700);
#702=CIRCLE('',#701,2.38125);
#703=CARTESIAN_POINT('',(14.31925,0.,-2.38125));
#704=VERTEX_POINT('',#703);
#705=EDGE_CURVE('E38',#704,#704,#702,.T.);
#706=ORIENTED_EDGE('',*,*,#705,.F.);
#707=EDGE_LOOP('',(#706));
#708=FACE_BOUND('',#707,.T.);
#709=CARTESIAN_POINT('',(14.31925,-1.21818411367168,7.5424991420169));
#710=CARTESIAN_POINT('',(14.31925,-1.18795567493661,7.22844262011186));
#711=CARTESIAN_POINT('',(14.31925,-1.15681855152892,6.91446649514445));
#712=CARTESIAN_POINT('',(14.31925,-1.09196773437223,6.28669213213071));
#713=CARTESIAN_POINT('',(14.31925,-1.05825331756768,5.97289396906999));
#714=CARTESIAN_POINT('',(14.31925,-0.987317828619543,5.34401119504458));
#715=CARTESIAN_POINT('',(14.31925,-0.950079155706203,5.02892855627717));
#716=CARTESIAN_POINT('',(14.31925,-0.870926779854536,4.39938727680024));
#717=CARTESIAN_POINT('',(14.31925,-0.829013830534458,4.08492854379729));
#718=CARTESIAN_POINT('',(14.31925,-0.760702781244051,3.61424659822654));
#719=CARTESIAN_POINT('',(14.31925,-0.737043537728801,3.45762712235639));
#720=CARTESIAN_POINT('',(14.31925,-0.687296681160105,3.14473575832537));
#721=CARTESIAN_POINT('',(14.31925,-0.661208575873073,2.98846394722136));
#722=CARTESIAN_POINT('',(14.31925,-0.605660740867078,2.67664906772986));
#723=CARTESIAN_POINT('',(14.31925,-0.576203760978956,2.52110551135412));
#724=CARTESIAN_POINT('',(14.31925,-0.5122298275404,2.21107669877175));
#725=CARTESIAN_POINT('',(14.31925,-0.477714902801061,2.05659104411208));
#726=CARTESIAN_POINT('',(14.31925,-0.418914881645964,1.82650574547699));
#727=CARTESIAN_POINT('',(14.31925,-0.398126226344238,1.75003044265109));
#728=CARTESIAN_POINT('',(14.31925,-0.352961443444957,1.59824076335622));
#729=CARTESIAN_POINT('',(14.31925,-0.328589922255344,1.52292503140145));
#730=CARTESIAN_POINT('',(14.31925,-0.279325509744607,1.38979499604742));
#731=CARTESIAN_POINT('',(14.31925,-0.255586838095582,1.33158768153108));
#732=CARTESIAN_POINT('',(14.31925,-0.214458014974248,1.24754275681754));
#733=CARTESIAN_POINT('',(14.31925,-0.199976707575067,1.22029429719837));
#734=CARTESIAN_POINT('',(14.31925,-0.168031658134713,1.16741716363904));
#735=CARTESIAN_POINT('',(14.31925,-0.150566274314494,1.1417893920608));
#736=CARTESIAN_POINT('',(14.31925,-0.120369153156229,1.1064106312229));
#737=CARTESIAN_POINT('',(14.31925,-0.109549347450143,1.09506170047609));
#738=CARTESIAN_POINT('',(14.31925,-0.086099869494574,1.07445337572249));
#739=CARTESIAN_POINT('',(14.31925,-0.0734872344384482,1.06517621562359));
#740=CARTESIAN_POINT('',(14.31925,-0.0537125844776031,1.05454865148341));
#741=CARTESIAN_POINT('',(14.31925,-0.0473935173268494,1.05165181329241));
#742=CARTESIAN_POINT('',(14.31925,-0.0343792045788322,1.04686864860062));
#743=CARTESIAN_POINT('',(14.31925,-0.0276842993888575,1.04498142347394));
#744=CARTESIAN_POINT('',(14.31925,-0.0139999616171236,1.04241512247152));
#745=CARTESIAN_POINT('',(14.31925,-0.0070085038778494,1.04174648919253));
#746=CARTESIAN_POINT('',(14.31925,0.00697523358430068,1.0417445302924));
#747=CARTESIAN_POINT('',(14.31925,0.0139675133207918,1.04241123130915));
#748=CARTESIAN_POINT('',(14.31925,0.0270666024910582,1.0448635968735));
#749=CARTESIAN_POINT('',(14.31925,0.0331950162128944,1.04653863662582));
#750=CARTESIAN_POINT('',(14.31925,0.0451455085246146,1.05074669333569));
#751=CARTESIAN_POINT('',(14.31925,0.0509674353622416,1.0532801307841));
#752=CARTESIAN_POINT('',(14.31925,0.0663679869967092,1.06111594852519));
#753=CARTESIAN_POINT('',(14.31925,0.0756009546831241,1.06709240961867));
#754=CARTESIAN_POINT('',(14.31925,0.0930817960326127,1.08034626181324));
#755=CARTESIAN_POINT('',(14.31925,0.101325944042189,1.08762833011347));
#756=CARTESIAN_POINT('',(14.31925,0.129859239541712,1.11557321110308));
#757=CARTESIAN_POINT('',(14.31925,0.147759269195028,1.13861598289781));
#758=CARTESIAN_POINT('',(14.31925,0.180410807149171,1.1868252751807));
#759=CARTESIAN_POINT('',(14.31925,0.195139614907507,1.2120054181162));
#760=CARTESIAN_POINT('',(14.31925,0.23645204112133,1.2893476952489));
#761=CARTESIAN_POINT('',(14.31925,0.260013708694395,1.34311478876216));
#762=CARTESIAN_POINT('',(14.31925,0.303160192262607,1.45224822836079));
#763=CARTESIAN_POINT('',(14.31925,0.32273290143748,1.50761887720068));
#764=CARTESIAN_POINT('',(14.31925,0.359320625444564,1.61930363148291));
#765=CARTESIAN_POINT('',(14.31925,0.376331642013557,1.67561906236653));
#766=CARTESIAN_POINT('',(14.31925,0.408537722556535,1.78866080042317));
#767=CARTESIAN_POINT('',(14.31925,0.423735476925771,1.84538636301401));
#768=CARTESIAN_POINT('',(14.31925,0.467056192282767,2.01484751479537));
#769=CARTESIAN_POINT('',(14.31925,0.493273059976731,2.12806935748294));
#770=CARTESIAN_POINT('',(14.31925,0.542500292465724,2.35521381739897));
#771=CARTESIAN_POINT('',(14.31925,0.565509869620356,2.46913659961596));
#772=CARTESIAN_POINT('',(14.31925,0.631238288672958,2.81180723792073));
#773=CARTESIAN_POINT('',(14.31925,0.670596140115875,3.0411966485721));
#774=CARTESIAN_POINT('',(14.31925,0.7440361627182,3.50031868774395));
#775=CARTESIAN_POINT('',(14.31925,0.778128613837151,3.73004974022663));
#776=CARTESIAN_POINT('',(14.31925,0.842723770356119,4.18988572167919));
#777=CARTESIAN_POINT('',(14.31925,0.873228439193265,4.41999037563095));
#778=CARTESIAN_POINT('',(14.31925,0.932944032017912,4.89083773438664));
#779=CARTESIAN_POINT('',(14.31925,0.962035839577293,5.13159536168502));
#780=CARTESIAN_POINT('',(14.31925,1.01805233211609,5.61340955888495));
#781=CARTESIAN_POINT('',(14.31925,1.0449765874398,5.85446617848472));
#782=CARTESIAN_POINT('',(14.31925,1.09708930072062,6.33663267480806));
#783=CARTESIAN_POINT('',(14.31925,1.12227869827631,6.5777424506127));
#784=CARTESIAN_POINT('',(14.31925,1.17122783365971,7.06005040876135));
#785=CARTESIAN_POINT('',(14.31925,1.19498790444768,7.30124855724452));
#786=CARTESIAN_POINT('',(14.31925,1.21818411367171,7.5424991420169));
#787=B_SPLINE_CURVE_WITH_KNOTS('',3,(#709,#710,#711,#712,#713,#714,#715,#716,#717,#718,#719,
#720,#721,#722,#723,#724,#725,#726,#727,#728,#729,#730,#731,#732,#733,#734,#735,#736,#737,#738,
#739,#740,#741,#742,#743,#744,#745,#746,#747,#748,#749,#750,#751,#752,#753,#754,#755,#756,#757,
#758,#759,#760,#761,#762,#763,#764,#765,#766,#767,#768,#769,#770,#771,#772,#773,#774,#775,#776,
#777,#778,#779,#780,#781,#782,#783,#784,#785,#786),.UNSPECIFIED.,.F.,.F.,(4,2,2,2,2,2,2,2,2,2,2,
2,2,2,2,2,2,2,2,2,2,2,2,2,2,2,2,2,2,2,2,2,2,2,2,2,2,2,4),(0.,0.946533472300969,1.89333347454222,
2.84514025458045,3.79679379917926,4.27197079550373,4.74724430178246,5.22213260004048,
5.6968309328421,5.93452009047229,6.171906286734,6.36010880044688,6.45262192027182,
6.54518610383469,6.59211113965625,6.63861684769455,6.65940444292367,6.68017350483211,
6.70111972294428,6.7220663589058,6.74105156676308,6.76004608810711,6.79284849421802,
6.82577084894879,6.91261873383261,7.00006902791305,7.17569954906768,7.35185543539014,
7.52828347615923,7.70444640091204,8.05300707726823,8.40165320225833,9.09974791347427,
9.79646197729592,10.4927929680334,11.2203079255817,11.9479667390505,12.6752283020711,
13.4023197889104),.UNSPECIFIED.);
#788=CARTESIAN_POINT('',(14.31925,-0.598003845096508,2.63906000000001));
#789=VERTEX_POINT('',#788);
#790=EDGE_CURVE('E205',#505,#789,#787,.T.);
#791=ORIENTED_EDGE('',*,*,#790,.F.);
#792=ORIENTED_EDGE('',*,*,#685,.F.);
#793=CARTESIAN_POINT('',(14.31925,0.598003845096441,2.63906000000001));
#794=VERTEX_POINT('',#793);
#795=EDGE_CURVE('E51',#794,#677,#787,.T.);
#796=ORIENTED_EDGE('',*,*,#795,.F.);
#797=DIRECTION('',(0.,1.,0.));
#798=VECTOR('',#797,1.);
#799=CARTESIAN_POINT('',(14.31925,0.,2.63906000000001));
#800=LINE('',#799,#798);
#801=EDGE_CURVE('E11',#789,#794,#800,.T.);
#802=ORIENTED_EDGE('',*,*,#801,.F.);
#803=EDGE_LOOP('',(#791,#792,#796,#802));
#804=FACE_BOUND('',#803,.T.);
#805=ADVANCED_FACE('F387',(#708,#804),#697,.T.);
#806=CARTESIAN_POINT('',(5.334,0.,-9.525));
#807=DIRECTION('',(0.,0.,-1.));
#808=DIRECTION('',(-1.,0.,0.));
#809=AXIS2_PLACEMENT_3D('',#806,#807,#808);
#810=CYLINDRICAL_SURFACE('',#809,3.0734);
#811=CARTESIAN_POINT('',(8.4074,0.,-2.01929999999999));
#812=CARTESIAN_POINT('',(8.40739769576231,0.101732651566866,-2.01929763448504));
#813=CARTESIAN_POINT('',(8.40230330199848,0.203487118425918,-2.01156814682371));
#814=CARTESIAN_POINT('',(8.38242696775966,0.403769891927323,-1.98111627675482));
#815=CARTESIAN_POINT('',(8.36763841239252,0.502295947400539,-1.95838365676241));
#816=CARTESIAN_POINT('',(8.32983954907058,0.692921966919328,-1.89930272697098));
#817=CARTESIAN_POINT('',(8.30686792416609,0.785049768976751,-1.86301844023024));
#818=CARTESIAN_POINT('',(8.25456289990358,0.961553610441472,-1.77836407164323));
#819=CARTESIAN_POINT('',(8.22522872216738,1.04592869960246,-1.72999251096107));
#820=CARTESIAN_POINT('',(8.15964609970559,1.21250971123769,-1.61811319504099));
#821=CARTESIAN_POINT('',(8.12302431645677,1.29394198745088,-1.55367699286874));
#822=CARTESIAN_POINT('',(8.04753547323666,1.44558097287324,-1.41369624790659));
#823=CARTESIAN_POINT('',(8.00866530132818,1.51577159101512,-1.33813607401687));
#824=CARTESIAN_POINT('',(7.9258934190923,1.65387111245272,-1.1646435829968));
#825=CARTESIAN_POINT('',(7.88212846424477,1.71979936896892,-1.065056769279));
#826=CARTESIAN_POINT('',(7.801303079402,1.83387431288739,-0.853717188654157));
#827=CARTESIAN_POINT('',(7.76423111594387,1.88205174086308,-0.741985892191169));
#828=CARTESIAN_POINT('',(7.7119677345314,1.94738073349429,-0.541345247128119));
#829=CARTESIAN_POINT('',(7.69355414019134,1.96945022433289,-0.45488432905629));
#830=CARTESIAN_POINT('',(7.66599214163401,2.00201596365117,-0.278427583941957));
#831=CARTESIAN_POINT('',(7.65682846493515,2.01253129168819,-0.188437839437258));
#832=CARTESIAN_POINT('',(7.6491750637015,2.02133454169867,-0.00705251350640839));
#833=CARTESIAN_POINT('',(7.65072484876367,2.01957720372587,0.0843470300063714));
#834=CARTESIAN_POINT('',(7.6643311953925,2.0038566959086,0.265323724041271));
#835=CARTESIAN_POINT('',(7.6763966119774,1.98988323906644,0.354899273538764));
#836=CARTESIAN_POINT('',(7.70854670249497,1.95138536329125,0.526408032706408));
#837=CARTESIAN_POINT('',(7.72830356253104,1.92728941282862,0.608502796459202));
#838=CARTESIAN_POINT('',(7.77358248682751,1.86964302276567,0.767576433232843));
#839=CARTESIAN_POINT('',(7.79910644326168,1.83608947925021,0.844553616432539));
#840=CARTESIAN_POINT('',(7.85919953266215,1.75279347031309,1.00760393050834));
#841=CARTESIAN_POINT('',(7.89455667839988,1.70115520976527,1.09241596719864));
#842=CARTESIAN_POINT('',(7.96714656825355,1.58648784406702,1.25315286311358));
#843=CARTESIAN_POINT('',(8.00438156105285,1.52344483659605,1.32906668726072));
#844=CARTESIAN_POINT('',(8.08536258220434,1.37277458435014,1.48564532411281));
#845=CARTESIAN_POINT('',(8.1288951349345,1.2827547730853,1.56414383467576));
#846=CARTESIAN_POINT('',(8.21009235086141,1.08854260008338,1.70499042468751));
#847=CARTESIAN_POINT('',(8.24776281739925,0.984364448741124,1.76735451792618));
#848=CARTESIAN_POINT('',(8.3066966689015,0.78573592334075,1.86274426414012));
#849=CARTESIAN_POINT('',(8.32973103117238,0.693427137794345,1.89913155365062));
#850=CARTESIAN_POINT('',(8.36752282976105,0.502920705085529,1.95820455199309));
#851=CARTESIAN_POINT('',(8.38228715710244,0.404728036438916,1.98090166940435));
#852=CARTESIAN_POINT('',(8.40222973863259,0.204674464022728,2.01145586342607));
#853=CARTESIAN_POINT('',(8.40737009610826,0.102800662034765,2.01925427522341));
#854=CARTESIAN_POINT('',(8.40742962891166,-0.100962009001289,2.01934530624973));
#855=CARTESIAN_POINT('',(8.40234898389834,-0.202850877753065,2.01163819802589));
#856=CARTESIAN_POINT('',(8.38312324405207,-0.396918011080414,1.982182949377));
#857=CARTESIAN_POINT('',(8.36957773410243,-0.489300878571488,1.9613629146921));
#858=CARTESIAN_POINT('',(8.33510518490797,-0.66897783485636,1.90757497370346));
#859=CARTESIAN_POINT('',(8.31417695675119,-0.756271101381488,1.87460511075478));
#860=CARTESIAN_POINT('',(8.26488584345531,-0.929706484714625,1.79524601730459));
#861=CARTESIAN_POINT('',(8.2361236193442,-1.0153928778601,1.74811508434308));
#862=CARTESIAN_POINT('',(8.17402619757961,-1.17797570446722,1.64296501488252));
#863=CARTESIAN_POINT('',(8.14068790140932,-1.25486611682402,1.58493849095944));
#864=CARTESIAN_POINT('',(8.06624147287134,-1.4103855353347,1.44935714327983));
#865=CARTESIAN_POINT('',(8.02473439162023,-1.48739922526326,1.37016708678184));
#866=CARTESIAN_POINT('',(7.94224825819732,-1.62771443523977,1.20011633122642));
#867=CARTESIAN_POINT('',(7.90126949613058,-1.69100870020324,1.10924949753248));
#868=CARTESIAN_POINT('',(7.82825690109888,-1.79670565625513,0.926991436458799));
#869=CARTESIAN_POINT('',(7.79573542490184,-1.84060940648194,0.836670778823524));
#870=CARTESIAN_POINT('',(7.73831078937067,-1.91501896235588,0.648437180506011));
#871=CARTESIAN_POINT('',(7.7133938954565,-1.94554896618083,0.550538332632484));
#872=CARTESIAN_POINT('',(7.67812773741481,-1.98783561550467,0.365463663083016));
#873=CARTESIAN_POINT('',(7.66606765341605,-2.00183885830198,0.2791355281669));
#874=CARTESIAN_POINT('',(7.65167688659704,-2.01848773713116,0.104614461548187));
#875=CARTESIAN_POINT('',(7.6493374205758,-2.02114362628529,0.0164232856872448));
#876=CARTESIAN_POINT('',(7.65474354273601,-2.0149316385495,-0.159204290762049));
#877=CARTESIAN_POINT('',(7.66248708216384,-2.00606610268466,-0.246640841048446));
#878=CARTESIAN_POINT('',(7.68688154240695,-1.97739194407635,-0.418454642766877));
#879=CARTESIAN_POINT('',(7.70354414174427,-1.95756897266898,-0.502827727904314));
#880=CARTESIAN_POINT('',(7.74935686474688,-1.90092148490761,-0.690038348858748));
#881=CARTESIAN_POINT('',(7.78070539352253,-1.86087516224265,-0.791354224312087));
#882=CARTESIAN_POINT('',(7.84983262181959,-1.76629545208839,-0.984574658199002));
#883=CARTESIAN_POINT('',(7.88762018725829,-1.71174203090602,-1.07646595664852));
#884=CARTESIAN_POINT('',(7.96610728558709,-1.58846740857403,-1.25138938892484));
#885=CARTESIAN_POINT('',(8.00684491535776,-1.51952477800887,-1.33424790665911));
#886=CARTESIAN_POINT('',(8.08699831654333,-1.36896539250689,-1.48832441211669));
#887=CARTESIAN_POINT('',(8.12641372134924,-1.28734515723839,-1.55953919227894));
#888=CARTESIAN_POINT('',(8.20502875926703,-1.10194227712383,-1.69649514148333));
#889=CARTESIAN_POINT('',(8.24365131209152,-0.996680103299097,-1.76059227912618));
#890=CARTESIAN_POINT('',(8.31070076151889,-0.773633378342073,-1.86932238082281));
#891=CARTESIAN_POINT('',(8.33914788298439,-0.655874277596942,-1.91399399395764));
#892=CARTESIAN_POINT('',(8.3758640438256,-0.44780065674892,-1.97104922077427));
#893=CARTESIAN_POINT('',(8.3876082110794,-0.359615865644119,-1.98906711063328));
#894=CARTESIAN_POINT('',(8.40337545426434,-0.180959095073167,-2.01319083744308));
#895=CARTESIAN_POINT('',(8.40740204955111,-0.0904881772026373,-2.01930210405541));
#896=CARTESIAN_POINT('',(8.4074,0.,-2.01929999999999));
#897=B_SPLINE_CURVE_WITH_KNOTS('',3,(#811,#812,#813,#814,#815,#816,#817,#818,#819,#820,#821,
#822,#823,#824,#825,#826,#827,#828,#829,#830,#831,#832,#833,#834,#835,#836,#837,#838,#839,#840,
#841,#842,#843,#844,#845,#846,#847,#848,#849,#850,#851,#852,#853,#854,#855,#856,#857,#858,#859,
#860,#861,#862,#863,#864,#865,#866,#867,#868,#869,#870,#871,#872,#873,#874,#875,#876,#877,#878,
#879,#880,#881,#882,#883,#884,#885,#886,#887,#888,#889,#890,#891,#892,#893,#894,#895,#896),
.UNSPECIFIED.,.T.,.F.,(4,2,2,2,2,2,2,2,2,2,2,2,2,2,2,2,2,2,2,2,2,2,2,2,2,2,2,2,2,2,2,2,2,2,2,2,
2,2,2,2,2,2,4),(0.,0.304831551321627,0.609871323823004,0.913487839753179,1.21714152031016,
1.5462292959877,1.8757839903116,2.25560015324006,2.63475543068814,2.90699929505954,
3.17879292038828,3.45158941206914,3.72461584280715,3.98709449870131,4.24965939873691,
4.56475175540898,4.88023082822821,5.25978143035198,5.63895386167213,5.94324908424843,
6.24729037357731,6.55252640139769,6.85775706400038,7.14349539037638,7.4292797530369,
7.73391456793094,8.03875668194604,8.39136371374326,8.74415675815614,9.05966078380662,
9.3745915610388,9.63827096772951,9.90171207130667,10.165099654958,10.4288329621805,
10.7671103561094,11.1058573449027,11.4502625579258,11.7947624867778,12.1800145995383,
12.564496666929,12.8357590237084,13.1068976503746),.UNSPECIFIED.);
#898=CARTESIAN_POINT('',(8.4074,0.,-2.01929999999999));
#899=VERTEX_POINT('',#898);
#900=EDGE_CURVE('E281',#899,#899,#897,.T.);
#901=ORIENTED_EDGE('',*,*,#900,.T.);
#902=EDGE_LOOP('',(#901));
#903=FACE_BOUND('',#902,.T.);
#904=CARTESIAN_POINT('',(5.334,0.,-2.63906));
#905=DIRECTION('',(0.,0.,-1.));
#906=DIRECTION('',(-1.,0.,0.));
#907=AXIS2_PLACEMENT_3D('',#904,#905,#906);
#908=CIRCLE('',#907,3.0734);
#909=CARTESIAN_POINT('',(2.2606,0.,-2.63906));
#910=VERTEX_POINT('',#909);
#911=EDGE_CURVE('E377',#910,#910,#908,.T.);
#912=ORIENTED_EDGE('',*,*,#911,.T.);
#913=EDGE_LOOP('',(#912));
#914=FACE_BOUND('',#913,.T.);
#915=CARTESIAN_POINT('',(5.334,0.,2.63906000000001));
#916=DIRECTION('',(0.,0.,1.));
#917=DIRECTION('',(1.,0.,0.));
#918=AXIS2_PLACEMENT_3D('',#915,#916,#917);
#919=CIRCLE('',#918,3.07340000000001);
#920=CARTESIAN_POINT('',(8.40740000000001,0.,2.63906000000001));
#921=VERTEX_POINT('',#920);
#922=EDGE_CURVE('E270',#921,#921,#919,.T.);
#923=ORIENTED_EDGE('',*,*,#922,.T.);
#924=EDGE_LOOP('',(#923));
#925=FACE_BOUND('',#924,.T.);
#926=ADVANCED_FACE('F296',(#903,#914,#925),#810,.F.);
#927=CARTESIAN_POINT('',(8.4074,0.,-2.63906));
#928=DIRECTION('',(0.,0.,1.));
#929=DIRECTION('',(1.,0.,0.));
#930=AXIS2_PLACEMENT_3D('',#927,#928,#929);
#931=PLANE('',#930);
#932=ORIENTED_EDGE('',*,*,#911,.F.);
#933=EDGE_LOOP('',(#932));
#934=FACE_BOUND('',#933,.T.);
#935=CARTESIAN_POINT('',(5.334,0.,-2.63906));
#936=DIRECTION('',(0.,0.,-1.));
#937=DIRECTION('',(-1.,0.,0.));
#938=AXIS2_PLACEMENT_3D('',#935,#936,#937);
#939=CIRCLE('',#938,3.76257573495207);
#940=CARTESIAN_POINT('',(1.57142426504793,0.,-2.63906));
#941=VERTEX_POINT('',#940);
#942=EDGE_CURVE('E380',#941,#941,#939,.T.);
#943=ORIENTED_EDGE('',*,*,#942,.T.);
#944=EDGE_LOOP('',(#943));
#945=FACE_BOUND('',#944,.T.);
#946=ADVANCED_FACE('F395',(#934,#945),#931,.F.);
#947=CARTESIAN_POINT('',(5.334,0.,-9.525));
#948=DIRECTION('',(0.,0.,-1.));
#949=DIRECTION('',(-1.,0.,0.));
#950=AXIS2_PLACEMENT_3D('',#947,#948,#949);
#951=CONICAL_SURFACE('',#950,3.96875,0.0299323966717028);
#952=ORIENTED_EDGE('',*,*,#942,.F.);
#953=EDGE_LOOP('',(#952));
#954=FACE_BOUND('',#953,.T.);
#955=ORIENTED_EDGE('',*,*,#157,.T.);
#956=EDGE_LOOP('',(#955));
#957=FACE_BOUND('',#956,.T.);
#958=ADVANCED_FACE('F421',(#954,#957),#951,.F.);
#959=CARTESIAN_POINT('',(18.034,0.,9.52500000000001));
#960=DIRECTION('',(0.,0.,1.));
#961=DIRECTION('',(1.,0.,0.));
#962=AXIS2_PLACEMENT_3D('',#959,#960,#961);
#963=CYLINDRICAL_SURFACE('',#962,3.07340000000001);
#964=ORIENTED_EDGE('',*,*,#559,.T.);
#965=CARTESIAN_POINT('',(18.034,0.,2.63906000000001));
#966=DIRECTION('',(0.,0.,1.));
#967=DIRECTION('',(1.,0.,0.));
#968=AXIS2_PLACEMENT_3D('',#965,#966,#967);
#969=CIRCLE('',#968,3.07340000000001);
#970=EDGE_CURVE('E243',#513,#558,#969,.T.);
#971=ORIENTED_EDGE('',*,*,#970,.T.);
#972=EDGE_LOOP('',(#964,#971));
#973=FACE_BOUND('',#972,.T.);
#974=ADVANCED_FACE('F213',(#973),#963,.F.);
#975=ORIENTED_EDGE('',*,*,#655,.T.);
#976=EDGE_CURVE('E234',#609,#654,#969,.T.);
#977=ORIENTED_EDGE('',*,*,#976,.T.);
#978=EDGE_LOOP('',(#975,#977));
#979=FACE_BOUND('',#978,.T.);
#980=ADVANCED_FACE('F174',(#979),#963,.F.);
#981=CARTESIAN_POINT('',(18.034,0.,9.52500000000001));
#982=DIRECTION('',(0.,0.,1.));
#983=DIRECTION('',(1.,0.,0.));
#984=AXIS2_PLACEMENT_3D('',#981,#982,#983);
#985=CONICAL_SURFACE('',#984,3.96875,0.0299323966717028);
#986=ORIENTED_EDGE('',*,*,#602,.T.);
#987=CARTESIAN_POINT('',(18.034,0.,2.63906000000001));
#988=DIRECTION('',(0.,0.,1.));
#989=DIRECTION('',(1.,0.,0.));
#990=AXIS2_PLACEMENT_3D('',#987,#988,#989);
#991=CIRCLE('',#990,3.76257573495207);
#992=EDGE_CURVE('E261',#503,#562,#991,.T.);
#993=ORIENTED_EDGE('',*,*,#992,.F.);
#994=ORIENTED_EDGE('',*,*,#506,.T.);
#995=ORIENTED_EDGE('',*,*,#790,.T.);
#996=EDGE_CURVE('E259',#794,#789,#991,.T.);
#997=ORIENTED_EDGE('',*,*,#996,.F.);
#998=ORIENTED_EDGE('',*,*,#795,.T.);
#999=ORIENTED_EDGE('',*,*,#678,.T.);
#1000=EDGE_CURVE('E238',#601,#658,#991,.T.);
#1001=ORIENTED_EDGE('',*,*,#1000,.F.);
#1002=EDGE_LOOP('',(#986,#993,#994,#995,#997,#998,#999,#1001));
#1003=FACE_BOUND('',#1002,.T.);
#1004=ORIENTED_EDGE('',*,*,#251,.T.);
#1005=EDGE_LOOP('',(#1004));
#1006=FACE_BOUND('',#1005,.T.);
#1007=ADVANCED_FACE('F168',(#1003,#1006),#985,.F.);
#1008=CARTESIAN_POINT('',(21.1074,0.,2.63906000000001));
#1009=DIRECTION('',(0.,0.,-1.));
#1010=DIRECTION('',(-1.,0.,0.));
#1011=AXIS2_PLACEMENT_3D('',#1008,#1009,#1010);
#1012=PLANE('',#1011);
#1013=ORIENTED_EDGE('',*,*,#659,.T.);
#1014=ORIENTED_EDGE('',*,*,#976,.F.);
#1015=ORIENTED_EDGE('',*,*,#610,.T.);
#1016=ORIENTED_EDGE('',*,*,#1000,.T.);
#1017=EDGE_LOOP('',(#1013,#1014,#1015,#1016));
#1018=FACE_BOUND('',#1017,.T.);
#1019=ADVANCED_FACE('F173',(#1018),#1012,.F.);
#1020=ORIENTED_EDGE('',*,*,#801,.T.);
#1021=ORIENTED_EDGE('',*,*,#996,.T.);
#1022=EDGE_LOOP('',(#1020,#1021));
#1023=FACE_BOUND('',#1022,.T.);
#1024=ADVANCED_FACE('F508',(#1023),#1012,.F.);
#1025=ORIENTED_EDGE('',*,*,#563,.T.);
#1026=ORIENTED_EDGE('',*,*,#970,.F.);
#1027=ORIENTED_EDGE('',*,*,#514,.T.);
#1028=ORIENTED_EDGE('',*,*,#992,.T.);
#1029=EDGE_LOOP('',(#1025,#1026,#1027,#1028));
#1030=FACE_BOUND('',#1029,.T.);
#1031=ADVANCED_FACE('F419',(#1030),#1012,.F.);
#1032=CARTESIAN_POINT('',(18.034,0.,-6.34999999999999));
#1033=DIRECTION('',(0.,0.,1.));
#1034=DIRECTION('',(1.,0.,0.));
#1035=AXIS2_PLACEMENT_3D('',#1032,#1033,#1034);
#1036=CONICAL_SURFACE('',#1035,3.0734,1.02974425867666);
#1037=CARTESIAN_POINT('',(18.034,0.,-8.1966850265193));
#1038=VERTEX_POINT('',#1037);
#1039=VERTEX_LOOP('',#1038);
#1040=FACE_BOUND('',#1039,.T.);
#1041=CARTESIAN_POINT('',(18.034,0.,-6.34999999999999));
#1042=DIRECTION('',(0.,0.,1.));
#1043=DIRECTION('',(1.,0.,0.));
#1044=AXIS2_PLACEMENT_3D('',#1041,#1042,#1043);
#1045=CIRCLE('',#1044,3.0734);
#1046=CARTESIAN_POINT('',(21.1074,0.,-6.34999999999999));
#1047=VERTEX_POINT('',#1046);
#1048=EDGE_CURVE('E242',#1047,#1047,#1045,.T.);
#1049=ORIENTED_EDGE('',*,*,#1048,.T.);
#1050=EDGE_LOOP('',(#1049));
#1051=FACE_BOUND('',#1050,.T.);
#1052=ADVANCED_FACE('F211',(#1040,#1051),#1036,.F.);
#1053=ORIENTED_EDGE('',*,*,#485,.T.);
#1054=EDGE_LOOP('',(#1053));
#1055=FACE_BOUND('',#1054,.T.);
#1056=ORIENTED_EDGE('',*,*,#1048,.F.);
#1057=EDGE_LOOP('',(#1056));
#1058=FACE_BOUND('',#1057,.T.);
#1059=ADVANCED_FACE('F207',(#1055,#1058),#963,.F.);
#1060=CARTESIAN_POINT('',(8.40740000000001,0.,2.63906000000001));
#1061=DIRECTION('',(0.,0.,-1.));
#1062=DIRECTION('',(-1.,0.,0.));
#1063=AXIS2_PLACEMENT_3D('',#1060,#1061,#1062);
#1064=PLANE('',#1063);
#1065=ORIENTED_EDGE('',*,*,#922,.F.);
#1066=EDGE_LOOP('',(#1065));
#1067=FACE_BOUND('',#1066,.T.);
#1068=CARTESIAN_POINT('',(5.334,0.,2.63906000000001));
#1069=DIRECTION('',(0.,0.,1.));
#1070=DIRECTION('',(1.,0.,0.));
#1071=AXIS2_PLACEMENT_3D('',#1068,#1069,#1070);
#1072=CIRCLE('',#1071,3.76257573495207);
#1073=CARTESIAN_POINT('',(9.09657573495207,0.,2.63906000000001));
#1074=VERTEX_POINT('',#1073);
#1075=EDGE_CURVE('E273',#1074,#1074,#1072,.T.);
#1076=ORIENTED_EDGE('',*,*,#1075,.T.);
#1077=EDGE_LOOP('',(#1076));
#1078=FACE_BOUND('',#1077,.T.);
#1079=ADVANCED_FACE('F175',(#1067,#1078),#1064,.F.);
#1080=CARTESIAN_POINT('',(5.334,0.,9.52500000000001));
#1081=DIRECTION('',(0.,0.,1.));
#1082=DIRECTION('',(1.,0.,0.));
#1083=AXIS2_PLACEMENT_3D('',#1080,#1081,#1082);
#1084=CONICAL_SURFACE('',#1083,3.96875,0.0299323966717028);
#1085=ORIENTED_EDGE('',*,*,#1075,.F.);
#1086=EDGE_LOOP('',(#1085));
#1087=FACE_BOUND('',#1086,.T.);
#1088=ORIENTED_EDGE('',*,*,#240,.T.);
#1089=EDGE_LOOP('',(#1088));
#1090=FACE_BOUND('',#1089,.T.);
#1091=ADVANCED_FACE('F304',(#1087,#1090),#1084,.F.);
#1092=CARTESIAN_POINT('',(30.95625,0.,0.));
#1093=DIRECTION('',(1.,0.,0.));
#1094=DIRECTION('',(0.,0.,-1.));
#1095=AXIS2_PLACEMENT_3D('',#1092,#1093,#1094);
#1096=CYLINDRICAL_SURFACE('',#1095,2.01929999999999);
#1097=CARTESIAN_POINT('',(11.688768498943,0.,0.));
#1098=DIRECTION('',(1.,0.,0.));
#1099=DIRECTION('',(0.,0.,-1.));
#1100=AXIS2_PLACEMENT_3D('',#1097,#1098,#1099);
#1101=CIRCLE('',#1100,2.01929999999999);
#1102=CARTESIAN_POINT('',(11.688768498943,0.,-2.01929999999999));
#1103=VERTEX_POINT('',#1102);
#1104=EDGE_CURVE('E284',#1103,#1103,#1101,.T.);
#1105=ORIENTED_EDGE('',*,*,#1104,.T.);
#1106=EDGE_LOOP('',(#1105));
#1107=FACE_BOUND('',#1106,.T.);
#1108=ORIENTED_EDGE('',*,*,#900,.F.);
#1109=EDGE_LOOP('',(#1108));
#1110=FACE_BOUND('',#1109,.T.);
#1111=ADVANCED_FACE('F299',(#1107,#1110),#1096,.F.);
#1112=CARTESIAN_POINT('',(11.90625,0.,0.));
#1113=DIRECTION('',(1.,0.,0.));
#1114=DIRECTION('',(0.,0.,-1.));
#1115=AXIS2_PLACEMENT_3D('',#1112,#1113,#1114);
#1116=CONICAL_SURFACE('',#1115,2.38124999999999,1.02974425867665);
#1117=CARTESIAN_POINT('',(11.90625,0.,0.));
#1118=DIRECTION('',(1.,0.,0.));
#1119=DIRECTION('',(0.,0.,-1.));
#1120=AXIS2_PLACEMENT_3D('',#1117,#1118,#1119);
#1121=CIRCLE('',#1120,2.38124999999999);
#1122=CARTESIAN_POINT('',(11.90625,0.,-2.38124999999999));
#1123=VERTEX_POINT('',#1122);
#1124=EDGE_CURVE('E282',#1123,#1123,#1121,.T.);
#1125=ORIENTED_EDGE('',*,*,#1124,.T.);
#1126=EDGE_LOOP('',(#1125));
#1127=FACE_BOUND('',#1126,.T.);
#1128=ORIENTED_EDGE('',*,*,#1104,.F.);
#1129=EDGE_LOOP('',(#1128));
#1130=FACE_BOUND('',#1129,.T.);
#1131=ADVANCED_FACE('F303',(#1127,#1130),#1116,.F.);
#1132=CARTESIAN_POINT('',(30.95625,0.,0.));
#1133=DIRECTION('',(1.,0.,0.));
#1134=DIRECTION('',(0.,0.,-1.));
#1135=AXIS2_PLACEMENT_3D('',#1132,#1133,#1134);
#1136=CYLINDRICAL_SURFACE('',#1135,2.38125);
#1137=ORIENTED_EDGE('',*,*,#705,.T.);
#1138=EDGE_LOOP('',(#1137));
#1139=FACE_BOUND('',#1138,.T.);
#1140=ORIENTED_EDGE('',*,*,#1124,.F.);
#1141=EDGE_LOOP('',(#1140));
#1142=FACE_BOUND('',#1141,.T.);
#1143=ADVANCED_FACE('F471',(#1139,#1142),#1136,.F.);
#1144=CLOSED_SHELL('',(#46,#113,#144,#179,#203,#227,#273,#290,#304,#316,#336,#356,#692,#805,
#926,#946,#958,#974,#980,#1007,#1019,#1024,#1031,#1052,#1059,#1079,#1091,#1111,#1131,#1143));
#1145=MANIFOLD_SOLID_BREP('B2',#1144);
#1146=ADVANCED_BREP_SHAPE_REPRESENTATION('',(#18,#1145),#14);
#1147=SHAPE_DEFINITION_REPRESENTATION(#9,#1146);
ENDSEC;
END-ISO-10303-21;
